VERSION 5.8 ;
BUSBITCHARS "[]" ;
DIVIDERCHAR "/" ;
UNITS
    DATABASE MICRONS 1000 ;
END UNITS

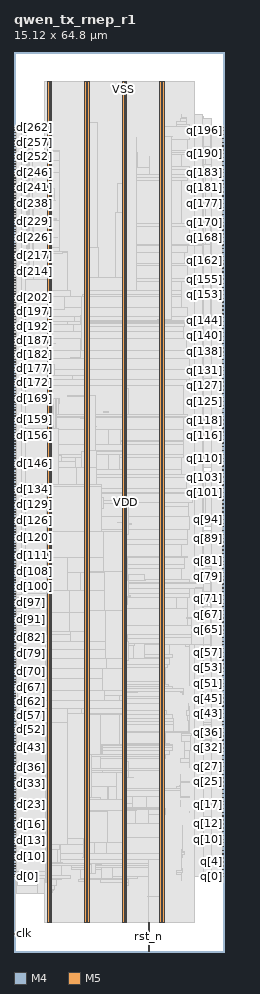
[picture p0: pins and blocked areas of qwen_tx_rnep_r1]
MACRO qwen_tx_rnep_r1
  FOREIGN qwen_tx_rnep_r1 0 0 ;
  CLASS BLOCK ;
  SIZE 15.12 BY 64.8 ;
  PIN clk
    DIRECTION INPUT ;
    USE SIGNAL ;
    PORT
      LAYER M4 ;
        RECT  0.054 1.296 0.138 1.32 ;
    END
    PORT
      LAYER M4 ;
        RECT  0.108 1.296 0.227 1.416 ;
    END
  END clk
  PIN d[0]
    DIRECTION INPUT ;
    USE SIGNAL ;
    PORT
      LAYER M4 ;
        RECT  0.054 5.424 0.138 5.448 ;
    END
  END d[0]
  PIN d[100]
    DIRECTION INPUT ;
    USE SIGNAL ;
    PORT
      LAYER M4 ;
        RECT  0.054 25.776 0.138 25.8 ;
    END
  END d[100]
  PIN d[101]
    DIRECTION INPUT ;
    USE SIGNAL ;
    PORT
      LAYER M4 ;
        RECT  0.054 25.968 0.138 25.992 ;
    END
  END d[101]
  PIN d[102]
    DIRECTION INPUT ;
    USE SIGNAL ;
    PORT
      LAYER M4 ;
        RECT  0.054 26.16 0.138 26.184 ;
    END
  END d[102]
  PIN d[103]
    DIRECTION INPUT ;
    USE SIGNAL ;
    PORT
      LAYER M4 ;
        RECT  0.054 26.4 0.138 26.424 ;
    END
  END d[103]
  PIN d[104]
    DIRECTION INPUT ;
    USE SIGNAL ;
    PORT
      LAYER M4 ;
        RECT  0.054 26.592 0.138 26.616 ;
    END
  END d[104]
  PIN d[105]
    DIRECTION INPUT ;
    USE SIGNAL ;
    PORT
      LAYER M4 ;
        RECT  0.054 26.784 0.138 26.808 ;
    END
  END d[105]
  PIN d[106]
    DIRECTION INPUT ;
    USE SIGNAL ;
    PORT
      LAYER M4 ;
        RECT  0.054 26.976 0.138 27 ;
    END
  END d[106]
  PIN d[107]
    DIRECTION INPUT ;
    USE SIGNAL ;
    PORT
      LAYER M4 ;
        RECT  0.054 27.168 0.138 27.192 ;
    END
  END d[107]
  PIN d[108]
    DIRECTION INPUT ;
    USE SIGNAL ;
    PORT
      LAYER M4 ;
        RECT  0.054 27.408 0.138 27.432 ;
    END
  END d[108]
  PIN d[109]
    DIRECTION INPUT ;
    USE SIGNAL ;
    PORT
      LAYER M4 ;
        RECT  0.054 27.6 0.138 27.624 ;
    END
  END d[109]
  PIN d[10]
    DIRECTION INPUT ;
    USE SIGNAL ;
    PORT
      LAYER M4 ;
        RECT  0.054 7.44 0.138 7.464 ;
    END
  END d[10]
  PIN d[110]
    DIRECTION INPUT ;
    USE SIGNAL ;
    PORT
      LAYER M4 ;
        RECT  0.054 27.792 0.138 27.816 ;
    END
  END d[110]
  PIN d[111]
    DIRECTION INPUT ;
    USE SIGNAL ;
    PORT
      LAYER M4 ;
        RECT  0.054 27.984 0.138 28.008 ;
    END
  END d[111]
  PIN d[112]
    DIRECTION INPUT ;
    USE SIGNAL ;
    PORT
      LAYER M4 ;
        RECT  0.054 28.224 0.138 28.248 ;
    END
  END d[112]
  PIN d[113]
    DIRECTION INPUT ;
    USE SIGNAL ;
    PORT
      LAYER M4 ;
        RECT  0.054 28.416 0.138 28.44 ;
    END
  END d[113]
  PIN d[114]
    DIRECTION INPUT ;
    USE SIGNAL ;
    PORT
      LAYER M4 ;
        RECT  0.054 28.608 0.138 28.632 ;
    END
  END d[114]
  PIN d[115]
    DIRECTION INPUT ;
    USE SIGNAL ;
    PORT
      LAYER M4 ;
        RECT  0.054 28.8 0.138 28.824 ;
    END
  END d[115]
  PIN d[116]
    DIRECTION INPUT ;
    USE SIGNAL ;
    PORT
      LAYER M4 ;
        RECT  0.054 29.04 0.138 29.064 ;
    END
  END d[116]
  PIN d[117]
    DIRECTION INPUT ;
    USE SIGNAL ;
    PORT
      LAYER M4 ;
        RECT  0.054 29.232 0.138 29.256 ;
    END
  END d[117]
  PIN d[118]
    DIRECTION INPUT ;
    USE SIGNAL ;
    PORT
      LAYER M4 ;
        RECT  0.054 29.424 0.138 29.448 ;
    END
  END d[118]
  PIN d[119]
    DIRECTION INPUT ;
    USE SIGNAL ;
    PORT
      LAYER M4 ;
        RECT  0.054 29.616 0.138 29.64 ;
    END
  END d[119]
  PIN d[11]
    DIRECTION INPUT ;
    USE SIGNAL ;
    PORT
      LAYER M4 ;
        RECT  0.054 7.632 0.138 7.656 ;
    END
  END d[11]
  PIN d[120]
    DIRECTION INPUT ;
    USE SIGNAL ;
    PORT
      LAYER M4 ;
        RECT  0.054 29.856 0.138 29.88 ;
    END
  END d[120]
  PIN d[121]
    DIRECTION INPUT ;
    USE SIGNAL ;
    PORT
      LAYER M4 ;
        RECT  0.054 30.048 0.138 30.072 ;
    END
  END d[121]
  PIN d[122]
    DIRECTION INPUT ;
    USE SIGNAL ;
    PORT
      LAYER M4 ;
        RECT  0.054 30.24 0.138 30.264 ;
    END
  END d[122]
  PIN d[123]
    DIRECTION INPUT ;
    USE SIGNAL ;
    PORT
      LAYER M4 ;
        RECT  0.054 30.432 0.138 30.456 ;
    END
  END d[123]
  PIN d[124]
    DIRECTION INPUT ;
    USE SIGNAL ;
    PORT
      LAYER M4 ;
        RECT  0.054 30.672 0.138 30.696 ;
    END
  END d[124]
  PIN d[125]
    DIRECTION INPUT ;
    USE SIGNAL ;
    PORT
      LAYER M4 ;
        RECT  0.054 30.864 0.138 30.888 ;
    END
  END d[125]
  PIN d[126]
    DIRECTION INPUT ;
    USE SIGNAL ;
    PORT
      LAYER M4 ;
        RECT  0.054 31.056 0.138 31.08 ;
    END
  END d[126]
  PIN d[127]
    DIRECTION INPUT ;
    USE SIGNAL ;
    PORT
      LAYER M4 ;
        RECT  0.054 31.248 0.138 31.272 ;
    END
  END d[127]
  PIN d[128]
    DIRECTION INPUT ;
    USE SIGNAL ;
    PORT
      LAYER M4 ;
        RECT  0.054 31.488 0.138 31.512 ;
    END
  END d[128]
  PIN d[129]
    DIRECTION INPUT ;
    USE SIGNAL ;
    PORT
      LAYER M4 ;
        RECT  0.054 31.68 0.138 31.704 ;
    END
  END d[129]
  PIN d[12]
    DIRECTION INPUT ;
    USE SIGNAL ;
    PORT
      LAYER M4 ;
        RECT  0.054 7.824 0.138 7.848 ;
    END
  END d[12]
  PIN d[130]
    DIRECTION INPUT ;
    USE SIGNAL ;
    PORT
      LAYER M4 ;
        RECT  0.054 31.872 0.138 31.896 ;
    END
  END d[130]
  PIN d[131]
    DIRECTION INPUT ;
    USE SIGNAL ;
    PORT
      LAYER M4 ;
        RECT  0.054 32.064 0.138 32.088 ;
    END
  END d[131]
  PIN d[132]
    DIRECTION INPUT ;
    USE SIGNAL ;
    PORT
      LAYER M4 ;
        RECT  0.054 32.304 0.138 32.328 ;
    END
  END d[132]
  PIN d[133]
    DIRECTION INPUT ;
    USE SIGNAL ;
    PORT
      LAYER M4 ;
        RECT  0.054 32.496 0.138 32.52 ;
    END
  END d[133]
  PIN d[134]
    DIRECTION INPUT ;
    USE SIGNAL ;
    PORT
      LAYER M4 ;
        RECT  0.054 32.688 0.138 32.712 ;
    END
  END d[134]
  PIN d[135]
    DIRECTION INPUT ;
    USE SIGNAL ;
    PORT
      LAYER M4 ;
        RECT  0.054 32.88 0.138 32.904 ;
    END
  END d[135]
  PIN d[136]
    DIRECTION INPUT ;
    USE SIGNAL ;
    PORT
      LAYER M4 ;
        RECT  0.054 33.12 0.138 33.144 ;
    END
  END d[136]
  PIN d[137]
    DIRECTION INPUT ;
    USE SIGNAL ;
    PORT
      LAYER M4 ;
        RECT  0.054 33.312 0.138 33.336 ;
    END
  END d[137]
  PIN d[138]
    DIRECTION INPUT ;
    USE SIGNAL ;
    PORT
      LAYER M4 ;
        RECT  0.054 33.504 0.138 33.528 ;
    END
  END d[138]
  PIN d[139]
    DIRECTION INPUT ;
    USE SIGNAL ;
    PORT
      LAYER M4 ;
        RECT  0.054 33.696 0.138 33.72 ;
    END
  END d[139]
  PIN d[13]
    DIRECTION INPUT ;
    USE SIGNAL ;
    PORT
      LAYER M4 ;
        RECT  0.054 8.016 0.138 8.04 ;
    END
  END d[13]
  PIN d[140]
    DIRECTION INPUT ;
    USE SIGNAL ;
    PORT
      LAYER M4 ;
        RECT  0.054 33.936 0.138 33.96 ;
    END
  END d[140]
  PIN d[141]
    DIRECTION INPUT ;
    USE SIGNAL ;
    PORT
      LAYER M4 ;
        RECT  0.054 34.128 0.138 34.152 ;
    END
  END d[141]
  PIN d[142]
    DIRECTION INPUT ;
    USE SIGNAL ;
    PORT
      LAYER M4 ;
        RECT  0.054 34.32 0.138 34.344 ;
    END
  END d[142]
  PIN d[143]
    DIRECTION INPUT ;
    USE SIGNAL ;
    PORT
      LAYER M4 ;
        RECT  0.054 34.512 0.138 34.536 ;
    END
  END d[143]
  PIN d[144]
    DIRECTION INPUT ;
    USE SIGNAL ;
    PORT
      LAYER M4 ;
        RECT  0.054 34.752 0.138 34.776 ;
    END
  END d[144]
  PIN d[145]
    DIRECTION INPUT ;
    USE SIGNAL ;
    PORT
      LAYER M4 ;
        RECT  0.054 34.944 0.138 34.968 ;
    END
  END d[145]
  PIN d[146]
    DIRECTION INPUT ;
    USE SIGNAL ;
    PORT
      LAYER M4 ;
        RECT  0.054 35.136 0.138 35.16 ;
    END
  END d[146]
  PIN d[147]
    DIRECTION INPUT ;
    USE SIGNAL ;
    PORT
      LAYER M4 ;
        RECT  0.054 35.328 0.138 35.352 ;
    END
  END d[147]
  PIN d[148]
    DIRECTION INPUT ;
    USE SIGNAL ;
    PORT
      LAYER M4 ;
        RECT  0.054 35.568 0.138 35.592 ;
    END
  END d[148]
  PIN d[149]
    DIRECTION INPUT ;
    USE SIGNAL ;
    PORT
      LAYER M4 ;
        RECT  0.054 35.76 0.138 35.784 ;
    END
  END d[149]
  PIN d[14]
    DIRECTION INPUT ;
    USE SIGNAL ;
    PORT
      LAYER M4 ;
        RECT  0.054 8.256 0.138 8.28 ;
    END
  END d[14]
  PIN d[150]
    DIRECTION INPUT ;
    USE SIGNAL ;
    PORT
      LAYER M4 ;
        RECT  0.054 35.952 0.138 35.976 ;
    END
  END d[150]
  PIN d[151]
    DIRECTION INPUT ;
    USE SIGNAL ;
    PORT
      LAYER M4 ;
        RECT  0.054 36.144 0.138 36.168 ;
    END
  END d[151]
  PIN d[152]
    DIRECTION INPUT ;
    USE SIGNAL ;
    PORT
      LAYER M4 ;
        RECT  0.054 36.384 0.138 36.408 ;
    END
  END d[152]
  PIN d[153]
    DIRECTION INPUT ;
    USE SIGNAL ;
    PORT
      LAYER M4 ;
        RECT  0.054 36.576 0.138 36.6 ;
    END
  END d[153]
  PIN d[154]
    DIRECTION INPUT ;
    USE SIGNAL ;
    PORT
      LAYER M4 ;
        RECT  0.054 36.768 0.138 36.792 ;
    END
  END d[154]
  PIN d[155]
    DIRECTION INPUT ;
    USE SIGNAL ;
    PORT
      LAYER M4 ;
        RECT  0.054 36.96 0.138 36.984 ;
    END
  END d[155]
  PIN d[156]
    DIRECTION INPUT ;
    USE SIGNAL ;
    PORT
      LAYER M4 ;
        RECT  0.054 37.2 0.138 37.224 ;
    END
  END d[156]
  PIN d[157]
    DIRECTION INPUT ;
    USE SIGNAL ;
    PORT
      LAYER M4 ;
        RECT  0.054 37.392 0.138 37.416 ;
    END
  END d[157]
  PIN d[158]
    DIRECTION INPUT ;
    USE SIGNAL ;
    PORT
      LAYER M4 ;
        RECT  0.054 37.584 0.138 37.608 ;
    END
  END d[158]
  PIN d[159]
    DIRECTION INPUT ;
    USE SIGNAL ;
    PORT
      LAYER M4 ;
        RECT  0.054 37.776 0.138 37.8 ;
    END
  END d[159]
  PIN d[15]
    DIRECTION INPUT ;
    USE SIGNAL ;
    PORT
      LAYER M4 ;
        RECT  0.054 8.448 0.138 8.472 ;
    END
  END d[15]
  PIN d[160]
    DIRECTION INPUT ;
    USE SIGNAL ;
    PORT
      LAYER M4 ;
        RECT  0.054 37.968 0.138 37.992 ;
    END
  END d[160]
  PIN d[161]
    DIRECTION INPUT ;
    USE SIGNAL ;
    PORT
      LAYER M4 ;
        RECT  0.054 38.208 0.138 38.232 ;
    END
  END d[161]
  PIN d[162]
    DIRECTION INPUT ;
    USE SIGNAL ;
    PORT
      LAYER M4 ;
        RECT  0.054 38.4 0.138 38.424 ;
    END
  END d[162]
  PIN d[163]
    DIRECTION INPUT ;
    USE SIGNAL ;
    PORT
      LAYER M4 ;
        RECT  0.054 38.592 0.138 38.616 ;
    END
  END d[163]
  PIN d[164]
    DIRECTION INPUT ;
    USE SIGNAL ;
    PORT
      LAYER M4 ;
        RECT  0.054 38.784 0.138 38.808 ;
    END
  END d[164]
  PIN d[165]
    DIRECTION INPUT ;
    USE SIGNAL ;
    PORT
      LAYER M4 ;
        RECT  0.054 39.024 0.138 39.048 ;
    END
  END d[165]
  PIN d[166]
    DIRECTION INPUT ;
    USE SIGNAL ;
    PORT
      LAYER M4 ;
        RECT  0.054 39.216 0.138 39.24 ;
    END
  END d[166]
  PIN d[167]
    DIRECTION INPUT ;
    USE SIGNAL ;
    PORT
      LAYER M4 ;
        RECT  0.054 39.408 0.138 39.432 ;
    END
  END d[167]
  PIN d[168]
    DIRECTION INPUT ;
    USE SIGNAL ;
    PORT
      LAYER M4 ;
        RECT  0.054 39.6 0.138 39.624 ;
    END
  END d[168]
  PIN d[169]
    DIRECTION INPUT ;
    USE SIGNAL ;
    PORT
      LAYER M4 ;
        RECT  0.054 39.84 0.138 39.864 ;
    END
  END d[169]
  PIN d[16]
    DIRECTION INPUT ;
    USE SIGNAL ;
    PORT
      LAYER M4 ;
        RECT  0.054 8.64 0.138 8.664 ;
    END
  END d[16]
  PIN d[170]
    DIRECTION INPUT ;
    USE SIGNAL ;
    PORT
      LAYER M4 ;
        RECT  0.054 40.032 0.138 40.056 ;
    END
  END d[170]
  PIN d[171]
    DIRECTION INPUT ;
    USE SIGNAL ;
    PORT
      LAYER M4 ;
        RECT  0.054 40.224 0.138 40.248 ;
    END
  END d[171]
  PIN d[172]
    DIRECTION INPUT ;
    USE SIGNAL ;
    PORT
      LAYER M4 ;
        RECT  0.054 40.416 0.138 40.44 ;
    END
  END d[172]
  PIN d[173]
    DIRECTION INPUT ;
    USE SIGNAL ;
    PORT
      LAYER M4 ;
        RECT  0.054 40.656 0.138 40.68 ;
    END
  END d[173]
  PIN d[174]
    DIRECTION INPUT ;
    USE SIGNAL ;
    PORT
      LAYER M4 ;
        RECT  0.054 40.848 0.138 40.872 ;
    END
  END d[174]
  PIN d[175]
    DIRECTION INPUT ;
    USE SIGNAL ;
    PORT
      LAYER M4 ;
        RECT  0.054 41.04 0.138 41.064 ;
    END
  END d[175]
  PIN d[176]
    DIRECTION INPUT ;
    USE SIGNAL ;
    PORT
      LAYER M4 ;
        RECT  0.054 41.232 0.138 41.256 ;
    END
  END d[176]
  PIN d[177]
    DIRECTION INPUT ;
    USE SIGNAL ;
    PORT
      LAYER M4 ;
        RECT  0.054 41.472 0.138 41.496 ;
    END
  END d[177]
  PIN d[178]
    DIRECTION INPUT ;
    USE SIGNAL ;
    PORT
      LAYER M4 ;
        RECT  0.054 41.664 0.138 41.688 ;
    END
  END d[178]
  PIN d[179]
    DIRECTION INPUT ;
    USE SIGNAL ;
    PORT
      LAYER M4 ;
        RECT  0.054 41.856 0.138 41.88 ;
    END
  END d[179]
  PIN d[17]
    DIRECTION INPUT ;
    USE SIGNAL ;
    PORT
      LAYER M4 ;
        RECT  0.054 8.832 0.138 8.856 ;
    END
  END d[17]
  PIN d[180]
    DIRECTION INPUT ;
    USE SIGNAL ;
    PORT
      LAYER M4 ;
        RECT  0.054 42.048 0.138 42.072 ;
    END
  END d[180]
  PIN d[181]
    DIRECTION INPUT ;
    USE SIGNAL ;
    PORT
      LAYER M4 ;
        RECT  0.054 42.288 0.138 42.312 ;
    END
  END d[181]
  PIN d[182]
    DIRECTION INPUT ;
    USE SIGNAL ;
    PORT
      LAYER M4 ;
        RECT  0.054 42.48 0.138 42.504 ;
    END
  END d[182]
  PIN d[183]
    DIRECTION INPUT ;
    USE SIGNAL ;
    PORT
      LAYER M4 ;
        RECT  0.054 42.672 0.138 42.696 ;
    END
  END d[183]
  PIN d[184]
    DIRECTION INPUT ;
    USE SIGNAL ;
    PORT
      LAYER M4 ;
        RECT  0.054 42.864 0.138 42.888 ;
    END
  END d[184]
  PIN d[185]
    DIRECTION INPUT ;
    USE SIGNAL ;
    PORT
      LAYER M4 ;
        RECT  0.054 43.104 0.138 43.128 ;
    END
  END d[185]
  PIN d[186]
    DIRECTION INPUT ;
    USE SIGNAL ;
    PORT
      LAYER M4 ;
        RECT  0.054 43.296 0.138 43.32 ;
    END
  END d[186]
  PIN d[187]
    DIRECTION INPUT ;
    USE SIGNAL ;
    PORT
      LAYER M4 ;
        RECT  0.054 43.488 0.138 43.512 ;
    END
  END d[187]
  PIN d[188]
    DIRECTION INPUT ;
    USE SIGNAL ;
    PORT
      LAYER M4 ;
        RECT  0.054 43.68 0.138 43.704 ;
    END
  END d[188]
  PIN d[189]
    DIRECTION INPUT ;
    USE SIGNAL ;
    PORT
      LAYER M4 ;
        RECT  0.054 43.92 0.138 43.944 ;
    END
  END d[189]
  PIN d[18]
    DIRECTION INPUT ;
    USE SIGNAL ;
    PORT
      LAYER M4 ;
        RECT  0.054 9.072 0.138 9.096 ;
    END
  END d[18]
  PIN d[190]
    DIRECTION INPUT ;
    USE SIGNAL ;
    PORT
      LAYER M4 ;
        RECT  0.054 44.112 0.138 44.136 ;
    END
  END d[190]
  PIN d[191]
    DIRECTION INPUT ;
    USE SIGNAL ;
    PORT
      LAYER M4 ;
        RECT  0.054 44.304 0.138 44.328 ;
    END
  END d[191]
  PIN d[192]
    DIRECTION INPUT ;
    USE SIGNAL ;
    PORT
      LAYER M4 ;
        RECT  0.054 44.496 0.138 44.52 ;
    END
  END d[192]
  PIN d[193]
    DIRECTION INPUT ;
    USE SIGNAL ;
    PORT
      LAYER M4 ;
        RECT  0.054 44.736 0.138 44.76 ;
    END
  END d[193]
  PIN d[194]
    DIRECTION INPUT ;
    USE SIGNAL ;
    PORT
      LAYER M4 ;
        RECT  0.054 44.928 0.138 44.952 ;
    END
  END d[194]
  PIN d[195]
    DIRECTION INPUT ;
    USE SIGNAL ;
    PORT
      LAYER M4 ;
        RECT  0.054 45.12 0.138 45.144 ;
    END
  END d[195]
  PIN d[196]
    DIRECTION INPUT ;
    USE SIGNAL ;
    PORT
      LAYER M4 ;
        RECT  0.054 45.312 0.138 45.336 ;
    END
  END d[196]
  PIN d[197]
    DIRECTION INPUT ;
    USE SIGNAL ;
    PORT
      LAYER M4 ;
        RECT  0.054 45.552 0.138 45.576 ;
    END
  END d[197]
  PIN d[198]
    DIRECTION INPUT ;
    USE SIGNAL ;
    PORT
      LAYER M4 ;
        RECT  0.054 45.744 0.138 45.768 ;
    END
  END d[198]
  PIN d[199]
    DIRECTION INPUT ;
    USE SIGNAL ;
    PORT
      LAYER M4 ;
        RECT  0.054 45.936 0.138 45.96 ;
    END
  END d[199]
  PIN d[19]
    DIRECTION INPUT ;
    USE SIGNAL ;
    PORT
      LAYER M4 ;
        RECT  0.054 9.264 0.138 9.288 ;
    END
  END d[19]
  PIN d[1]
    DIRECTION INPUT ;
    USE SIGNAL ;
    PORT
      LAYER M4 ;
        RECT  0.054 5.568 0.138 5.592 ;
    END
  END d[1]
  PIN d[200]
    DIRECTION INPUT ;
    USE SIGNAL ;
    PORT
      LAYER M4 ;
        RECT  0.054 46.128 0.138 46.152 ;
    END
  END d[200]
  PIN d[201]
    DIRECTION INPUT ;
    USE SIGNAL ;
    PORT
      LAYER M4 ;
        RECT  0.054 46.368 0.138 46.392 ;
    END
  END d[201]
  PIN d[202]
    DIRECTION INPUT ;
    USE SIGNAL ;
    PORT
      LAYER M4 ;
        RECT  0.054 46.56 0.138 46.584 ;
    END
  END d[202]
  PIN d[203]
    DIRECTION INPUT ;
    USE SIGNAL ;
    PORT
      LAYER M4 ;
        RECT  0.054 46.752 0.138 46.776 ;
    END
  END d[203]
  PIN d[204]
    DIRECTION INPUT ;
    USE SIGNAL ;
    PORT
      LAYER M4 ;
        RECT  0.054 46.944 0.138 46.968 ;
    END
  END d[204]
  PIN d[205]
    DIRECTION INPUT ;
    USE SIGNAL ;
    PORT
      LAYER M4 ;
        RECT  0.054 47.184 0.138 47.208 ;
    END
  END d[205]
  PIN d[206]
    DIRECTION INPUT ;
    USE SIGNAL ;
    PORT
      LAYER M4 ;
        RECT  0.054 47.376 0.138 47.4 ;
    END
  END d[206]
  PIN d[207]
    DIRECTION INPUT ;
    USE SIGNAL ;
    PORT
      LAYER M4 ;
        RECT  0.054 47.568 0.138 47.592 ;
    END
  END d[207]
  PIN d[208]
    DIRECTION INPUT ;
    USE SIGNAL ;
    PORT
      LAYER M4 ;
        RECT  0.054 47.76 0.138 47.784 ;
    END
  END d[208]
  PIN d[209]
    DIRECTION INPUT ;
    USE SIGNAL ;
    PORT
      LAYER M4 ;
        RECT  0.054 48 0.138 48.024 ;
    END
  END d[209]
  PIN d[20]
    DIRECTION INPUT ;
    USE SIGNAL ;
    PORT
      LAYER M4 ;
        RECT  0.054 9.456 0.138 9.48 ;
    END
  END d[20]
  PIN d[210]
    DIRECTION INPUT ;
    USE SIGNAL ;
    PORT
      LAYER M4 ;
        RECT  0.054 48.192 0.138 48.216 ;
    END
  END d[210]
  PIN d[211]
    DIRECTION INPUT ;
    USE SIGNAL ;
    PORT
      LAYER M4 ;
        RECT  0.054 48.384 0.138 48.408 ;
    END
  END d[211]
  PIN d[212]
    DIRECTION INPUT ;
    USE SIGNAL ;
    PORT
      LAYER M4 ;
        RECT  0.054 48.576 0.138 48.6 ;
    END
  END d[212]
  PIN d[213]
    DIRECTION INPUT ;
    USE SIGNAL ;
    PORT
      LAYER M4 ;
        RECT  0.054 48.768 0.138 48.792 ;
    END
  END d[213]
  PIN d[214]
    DIRECTION INPUT ;
    USE SIGNAL ;
    PORT
      LAYER M4 ;
        RECT  0.054 49.008 0.138 49.032 ;
    END
  END d[214]
  PIN d[215]
    DIRECTION INPUT ;
    USE SIGNAL ;
    PORT
      LAYER M4 ;
        RECT  0.054 49.2 0.138 49.224 ;
    END
  END d[215]
  PIN d[216]
    DIRECTION INPUT ;
    USE SIGNAL ;
    PORT
      LAYER M4 ;
        RECT  0.054 49.392 0.138 49.416 ;
    END
  END d[216]
  PIN d[217]
    DIRECTION INPUT ;
    USE SIGNAL ;
    PORT
      LAYER M4 ;
        RECT  0.054 49.584 0.138 49.608 ;
    END
  END d[217]
  PIN d[218]
    DIRECTION INPUT ;
    USE SIGNAL ;
    PORT
      LAYER M4 ;
        RECT  0.054 49.824 0.138 49.848 ;
    END
  END d[218]
  PIN d[219]
    DIRECTION INPUT ;
    USE SIGNAL ;
    PORT
      LAYER M4 ;
        RECT  0.054 50.016 0.138 50.04 ;
    END
  END d[219]
  PIN d[21]
    DIRECTION INPUT ;
    USE SIGNAL ;
    PORT
      LAYER M4 ;
        RECT  0.054 9.648 0.138 9.672 ;
    END
  END d[21]
  PIN d[220]
    DIRECTION INPUT ;
    USE SIGNAL ;
    PORT
      LAYER M4 ;
        RECT  0.054 50.208 0.138 50.232 ;
    END
  END d[220]
  PIN d[221]
    DIRECTION INPUT ;
    USE SIGNAL ;
    PORT
      LAYER M4 ;
        RECT  0.054 50.4 0.138 50.424 ;
    END
  END d[221]
  PIN d[222]
    DIRECTION INPUT ;
    USE SIGNAL ;
    PORT
      LAYER M4 ;
        RECT  0.054 50.64 0.138 50.664 ;
    END
  END d[222]
  PIN d[223]
    DIRECTION INPUT ;
    USE SIGNAL ;
    PORT
      LAYER M4 ;
        RECT  0.054 50.832 0.138 50.856 ;
    END
  END d[223]
  PIN d[224]
    DIRECTION INPUT ;
    USE SIGNAL ;
    PORT
      LAYER M4 ;
        RECT  0.054 51.024 0.138 51.048 ;
    END
  END d[224]
  PIN d[225]
    DIRECTION INPUT ;
    USE SIGNAL ;
    PORT
      LAYER M4 ;
        RECT  0.054 51.216 0.138 51.24 ;
    END
  END d[225]
  PIN d[226]
    DIRECTION INPUT ;
    USE SIGNAL ;
    PORT
      LAYER M4 ;
        RECT  0.054 51.456 0.138 51.48 ;
    END
  END d[226]
  PIN d[227]
    DIRECTION INPUT ;
    USE SIGNAL ;
    PORT
      LAYER M4 ;
        RECT  0.054 51.648 0.138 51.672 ;
    END
  END d[227]
  PIN d[228]
    DIRECTION INPUT ;
    USE SIGNAL ;
    PORT
      LAYER M4 ;
        RECT  0.054 51.84 0.138 51.864 ;
    END
  END d[228]
  PIN d[229]
    DIRECTION INPUT ;
    USE SIGNAL ;
    PORT
      LAYER M4 ;
        RECT  0.054 52.032 0.138 52.056 ;
    END
  END d[229]
  PIN d[22]
    DIRECTION INPUT ;
    USE SIGNAL ;
    PORT
      LAYER M4 ;
        RECT  0.054 9.888 0.138 9.912 ;
    END
  END d[22]
  PIN d[230]
    DIRECTION INPUT ;
    USE SIGNAL ;
    PORT
      LAYER M4 ;
        RECT  0.054 52.272 0.138 52.296 ;
    END
  END d[230]
  PIN d[231]
    DIRECTION INPUT ;
    USE SIGNAL ;
    PORT
      LAYER M4 ;
        RECT  0.054 52.464 0.138 52.488 ;
    END
  END d[231]
  PIN d[232]
    DIRECTION INPUT ;
    USE SIGNAL ;
    PORT
      LAYER M4 ;
        RECT  0.054 52.656 0.138 52.68 ;
    END
  END d[232]
  PIN d[233]
    DIRECTION INPUT ;
    USE SIGNAL ;
    PORT
      LAYER M4 ;
        RECT  0.054 52.848 0.138 52.872 ;
    END
  END d[233]
  PIN d[234]
    DIRECTION INPUT ;
    USE SIGNAL ;
    PORT
      LAYER M4 ;
        RECT  0.054 53.088 0.138 53.112 ;
    END
  END d[234]
  PIN d[235]
    DIRECTION INPUT ;
    USE SIGNAL ;
    PORT
      LAYER M4 ;
        RECT  0.054 53.28 0.138 53.304 ;
    END
  END d[235]
  PIN d[236]
    DIRECTION INPUT ;
    USE SIGNAL ;
    PORT
      LAYER M4 ;
        RECT  0.054 53.472 0.138 53.496 ;
    END
  END d[236]
  PIN d[237]
    DIRECTION INPUT ;
    USE SIGNAL ;
    PORT
      LAYER M4 ;
        RECT  0.054 53.664 0.138 53.688 ;
    END
  END d[237]
  PIN d[238]
    DIRECTION INPUT ;
    USE SIGNAL ;
    PORT
      LAYER M4 ;
        RECT  0.054 53.904 0.138 53.928 ;
    END
  END d[238]
  PIN d[239]
    DIRECTION INPUT ;
    USE SIGNAL ;
    PORT
      LAYER M4 ;
        RECT  0.054 54.096 0.138 54.12 ;
    END
  END d[239]
  PIN d[23]
    DIRECTION INPUT ;
    USE SIGNAL ;
    PORT
      LAYER M4 ;
        RECT  0.054 10.08 0.138 10.104 ;
    END
  END d[23]
  PIN d[240]
    DIRECTION INPUT ;
    USE SIGNAL ;
    PORT
      LAYER M4 ;
        RECT  0.054 54.288 0.138 54.312 ;
    END
  END d[240]
  PIN d[241]
    DIRECTION INPUT ;
    USE SIGNAL ;
    PORT
      LAYER M4 ;
        RECT  0.054 54.48 0.138 54.504 ;
    END
  END d[241]
  PIN d[242]
    DIRECTION INPUT ;
    USE SIGNAL ;
    PORT
      LAYER M4 ;
        RECT  0.054 54.72 0.138 54.744 ;
    END
  END d[242]
  PIN d[243]
    DIRECTION INPUT ;
    USE SIGNAL ;
    PORT
      LAYER M4 ;
        RECT  0.054 54.912 0.138 54.936 ;
    END
  END d[243]
  PIN d[244]
    DIRECTION INPUT ;
    USE SIGNAL ;
    PORT
      LAYER M4 ;
        RECT  0.054 55.104 0.138 55.128 ;
    END
  END d[244]
  PIN d[245]
    DIRECTION INPUT ;
    USE SIGNAL ;
    PORT
      LAYER M4 ;
        RECT  0.054 55.296 0.138 55.32 ;
    END
  END d[245]
  PIN d[246]
    DIRECTION INPUT ;
    USE SIGNAL ;
    PORT
      LAYER M4 ;
        RECT  0.054 55.536 0.138 55.56 ;
    END
  END d[246]
  PIN d[247]
    DIRECTION INPUT ;
    USE SIGNAL ;
    PORT
      LAYER M4 ;
        RECT  0.054 55.728 0.138 55.752 ;
    END
  END d[247]
  PIN d[248]
    DIRECTION INPUT ;
    USE SIGNAL ;
    PORT
      LAYER M4 ;
        RECT  0.054 55.92 0.138 55.944 ;
    END
  END d[248]
  PIN d[249]
    DIRECTION INPUT ;
    USE SIGNAL ;
    PORT
      LAYER M4 ;
        RECT  0.054 56.112 0.138 56.136 ;
    END
  END d[249]
  PIN d[24]
    DIRECTION INPUT ;
    USE SIGNAL ;
    PORT
      LAYER M4 ;
        RECT  0.054 10.272 0.138 10.296 ;
    END
  END d[24]
  PIN d[250]
    DIRECTION INPUT ;
    USE SIGNAL ;
    PORT
      LAYER M4 ;
        RECT  0.054 56.352 0.138 56.376 ;
    END
  END d[250]
  PIN d[251]
    DIRECTION INPUT ;
    USE SIGNAL ;
    PORT
      LAYER M4 ;
        RECT  0.054 56.544 0.138 56.568 ;
    END
  END d[251]
  PIN d[252]
    DIRECTION INPUT ;
    USE SIGNAL ;
    PORT
      LAYER M4 ;
        RECT  0.054 56.736 0.138 56.76 ;
    END
  END d[252]
  PIN d[253]
    DIRECTION INPUT ;
    USE SIGNAL ;
    PORT
      LAYER M4 ;
        RECT  0.054 56.928 0.138 56.952 ;
    END
  END d[253]
  PIN d[254]
    DIRECTION INPUT ;
    USE SIGNAL ;
    PORT
      LAYER M4 ;
        RECT  0.054 57.168 0.138 57.192 ;
    END
  END d[254]
  PIN d[255]
    DIRECTION INPUT ;
    USE SIGNAL ;
    PORT
      LAYER M4 ;
        RECT  0.054 57.36 0.138 57.384 ;
    END
  END d[255]
  PIN d[256]
    DIRECTION INPUT ;
    USE SIGNAL ;
    PORT
      LAYER M4 ;
        RECT  0.054 57.552 0.138 57.576 ;
    END
  END d[256]
  PIN d[257]
    DIRECTION INPUT ;
    USE SIGNAL ;
    PORT
      LAYER M4 ;
        RECT  0.054 57.744 0.138 57.768 ;
    END
  END d[257]
  PIN d[258]
    DIRECTION INPUT ;
    USE SIGNAL ;
    PORT
      LAYER M4 ;
        RECT  0.054 57.984 0.138 58.008 ;
    END
  END d[258]
  PIN d[259]
    DIRECTION INPUT ;
    USE SIGNAL ;
    PORT
      LAYER M4 ;
        RECT  0.054 58.176 0.138 58.2 ;
    END
  END d[259]
  PIN d[25]
    DIRECTION INPUT ;
    USE SIGNAL ;
    PORT
      LAYER M4 ;
        RECT  0.054 10.464 0.138 10.488 ;
    END
  END d[25]
  PIN d[260]
    DIRECTION INPUT ;
    USE SIGNAL ;
    PORT
      LAYER M4 ;
        RECT  0.054 58.368 0.138 58.392 ;
    END
  END d[260]
  PIN d[261]
    DIRECTION INPUT ;
    USE SIGNAL ;
    PORT
      LAYER M4 ;
        RECT  0.054 58.56 0.138 58.584 ;
    END
  END d[261]
  PIN d[262]
    DIRECTION INPUT ;
    USE SIGNAL ;
    PORT
      LAYER M4 ;
        RECT  0.054 58.8 0.138 58.824 ;
    END
  END d[262]
  PIN d[263]
    DIRECTION INPUT ;
    USE SIGNAL ;
    PORT
      LAYER M4 ;
        RECT  0.054 58.992 0.138 59.016 ;
    END
  END d[263]
  PIN d[264]
    DIRECTION INPUT ;
    USE SIGNAL ;
    PORT
      LAYER M4 ;
        RECT  0.054 59.184 0.138 59.208 ;
    END
  END d[264]
  PIN d[265]
    DIRECTION INPUT ;
    USE SIGNAL ;
    PORT
      LAYER M4 ;
        RECT  0.054 59.376 0.138 59.4 ;
    END
  END d[265]
  PIN d[26]
    DIRECTION INPUT ;
    USE SIGNAL ;
    PORT
      LAYER M4 ;
        RECT  0.054 10.704 0.138 10.728 ;
    END
  END d[26]
  PIN d[27]
    DIRECTION INPUT ;
    USE SIGNAL ;
    PORT
      LAYER M4 ;
        RECT  0.054 10.896 0.138 10.92 ;
    END
  END d[27]
  PIN d[28]
    DIRECTION INPUT ;
    USE SIGNAL ;
    PORT
      LAYER M4 ;
        RECT  0.054 11.088 0.138 11.112 ;
    END
  END d[28]
  PIN d[29]
    DIRECTION INPUT ;
    USE SIGNAL ;
    PORT
      LAYER M4 ;
        RECT  0.054 11.28 0.138 11.304 ;
    END
  END d[29]
  PIN d[2]
    DIRECTION INPUT ;
    USE SIGNAL ;
    PORT
      LAYER M4 ;
        RECT  0.054 5.808 0.138 5.832 ;
    END
  END d[2]
  PIN d[30]
    DIRECTION INPUT ;
    USE SIGNAL ;
    PORT
      LAYER M4 ;
        RECT  0.054 11.52 0.138 11.544 ;
    END
  END d[30]
  PIN d[31]
    DIRECTION INPUT ;
    USE SIGNAL ;
    PORT
      LAYER M4 ;
        RECT  0.054 11.712 0.138 11.736 ;
    END
  END d[31]
  PIN d[32]
    DIRECTION INPUT ;
    USE SIGNAL ;
    PORT
      LAYER M4 ;
        RECT  0.054 11.904 0.138 11.928 ;
    END
  END d[32]
  PIN d[33]
    DIRECTION INPUT ;
    USE SIGNAL ;
    PORT
      LAYER M4 ;
        RECT  0.054 12.096 0.138 12.12 ;
    END
  END d[33]
  PIN d[34]
    DIRECTION INPUT ;
    USE SIGNAL ;
    PORT
      LAYER M4 ;
        RECT  0.054 12.336 0.138 12.36 ;
    END
  END d[34]
  PIN d[35]
    DIRECTION INPUT ;
    USE SIGNAL ;
    PORT
      LAYER M4 ;
        RECT  0.054 12.528 0.138 12.552 ;
    END
  END d[35]
  PIN d[36]
    DIRECTION INPUT ;
    USE SIGNAL ;
    PORT
      LAYER M4 ;
        RECT  0.054 12.72 0.138 12.744 ;
    END
  END d[36]
  PIN d[37]
    DIRECTION INPUT ;
    USE SIGNAL ;
    PORT
      LAYER M4 ;
        RECT  0.054 12.912 0.138 12.936 ;
    END
  END d[37]
  PIN d[38]
    DIRECTION INPUT ;
    USE SIGNAL ;
    PORT
      LAYER M4 ;
        RECT  0.054 13.152 0.138 13.176 ;
    END
  END d[38]
  PIN d[39]
    DIRECTION INPUT ;
    USE SIGNAL ;
    PORT
      LAYER M4 ;
        RECT  0.054 13.344 0.138 13.368 ;
    END
  END d[39]
  PIN d[3]
    DIRECTION INPUT ;
    USE SIGNAL ;
    PORT
      LAYER M4 ;
        RECT  0.054 6 0.138 6.024 ;
    END
  END d[3]
  PIN d[40]
    DIRECTION INPUT ;
    USE SIGNAL ;
    PORT
      LAYER M4 ;
        RECT  0.054 13.536 0.138 13.56 ;
    END
  END d[40]
  PIN d[41]
    DIRECTION INPUT ;
    USE SIGNAL ;
    PORT
      LAYER M4 ;
        RECT  0.054 13.728 0.138 13.752 ;
    END
  END d[41]
  PIN d[42]
    DIRECTION INPUT ;
    USE SIGNAL ;
    PORT
      LAYER M4 ;
        RECT  0.054 13.968 0.138 13.992 ;
    END
  END d[42]
  PIN d[43]
    DIRECTION INPUT ;
    USE SIGNAL ;
    PORT
      LAYER M4 ;
        RECT  0.054 14.16 0.138 14.184 ;
    END
  END d[43]
  PIN d[44]
    DIRECTION INPUT ;
    USE SIGNAL ;
    PORT
      LAYER M4 ;
        RECT  0.054 14.352 0.138 14.376 ;
    END
  END d[44]
  PIN d[45]
    DIRECTION INPUT ;
    USE SIGNAL ;
    PORT
      LAYER M4 ;
        RECT  0.054 14.544 0.138 14.568 ;
    END
  END d[45]
  PIN d[46]
    DIRECTION INPUT ;
    USE SIGNAL ;
    PORT
      LAYER M4 ;
        RECT  0.054 14.784 0.138 14.808 ;
    END
  END d[46]
  PIN d[47]
    DIRECTION INPUT ;
    USE SIGNAL ;
    PORT
      LAYER M4 ;
        RECT  0.054 14.976 0.138 15 ;
    END
  END d[47]
  PIN d[48]
    DIRECTION INPUT ;
    USE SIGNAL ;
    PORT
      LAYER M4 ;
        RECT  0.054 15.168 0.138 15.192 ;
    END
  END d[48]
  PIN d[49]
    DIRECTION INPUT ;
    USE SIGNAL ;
    PORT
      LAYER M4 ;
        RECT  0.054 15.36 0.138 15.384 ;
    END
  END d[49]
  PIN d[4]
    DIRECTION INPUT ;
    USE SIGNAL ;
    PORT
      LAYER M4 ;
        RECT  0.054 6.192 0.138 6.216 ;
    END
  END d[4]
  PIN d[50]
    DIRECTION INPUT ;
    USE SIGNAL ;
    PORT
      LAYER M4 ;
        RECT  0.054 15.6 0.138 15.624 ;
    END
  END d[50]
  PIN d[51]
    DIRECTION INPUT ;
    USE SIGNAL ;
    PORT
      LAYER M4 ;
        RECT  0.054 15.792 0.138 15.816 ;
    END
  END d[51]
  PIN d[52]
    DIRECTION INPUT ;
    USE SIGNAL ;
    PORT
      LAYER M4 ;
        RECT  0.054 15.984 0.138 16.008 ;
    END
  END d[52]
  PIN d[53]
    DIRECTION INPUT ;
    USE SIGNAL ;
    PORT
      LAYER M4 ;
        RECT  0.054 16.176 0.138 16.2 ;
    END
  END d[53]
  PIN d[54]
    DIRECTION INPUT ;
    USE SIGNAL ;
    PORT
      LAYER M4 ;
        RECT  0.054 16.368 0.138 16.392 ;
    END
  END d[54]
  PIN d[55]
    DIRECTION INPUT ;
    USE SIGNAL ;
    PORT
      LAYER M4 ;
        RECT  0.054 16.608 0.138 16.632 ;
    END
  END d[55]
  PIN d[56]
    DIRECTION INPUT ;
    USE SIGNAL ;
    PORT
      LAYER M4 ;
        RECT  0.054 16.8 0.138 16.824 ;
    END
  END d[56]
  PIN d[57]
    DIRECTION INPUT ;
    USE SIGNAL ;
    PORT
      LAYER M4 ;
        RECT  0.054 16.992 0.138 17.016 ;
    END
  END d[57]
  PIN d[58]
    DIRECTION INPUT ;
    USE SIGNAL ;
    PORT
      LAYER M4 ;
        RECT  0.054 17.184 0.138 17.208 ;
    END
  END d[58]
  PIN d[59]
    DIRECTION INPUT ;
    USE SIGNAL ;
    PORT
      LAYER M4 ;
        RECT  0.054 17.424 0.138 17.448 ;
    END
  END d[59]
  PIN d[5]
    DIRECTION INPUT ;
    USE SIGNAL ;
    PORT
      LAYER M4 ;
        RECT  0.054 6.384 0.138 6.408 ;
    END
  END d[5]
  PIN d[60]
    DIRECTION INPUT ;
    USE SIGNAL ;
    PORT
      LAYER M4 ;
        RECT  0.054 17.616 0.138 17.64 ;
    END
  END d[60]
  PIN d[61]
    DIRECTION INPUT ;
    USE SIGNAL ;
    PORT
      LAYER M4 ;
        RECT  0.054 17.808 0.138 17.832 ;
    END
  END d[61]
  PIN d[62]
    DIRECTION INPUT ;
    USE SIGNAL ;
    PORT
      LAYER M4 ;
        RECT  0.054 18 0.138 18.024 ;
    END
  END d[62]
  PIN d[63]
    DIRECTION INPUT ;
    USE SIGNAL ;
    PORT
      LAYER M4 ;
        RECT  0.054 18.24 0.138 18.264 ;
    END
  END d[63]
  PIN d[64]
    DIRECTION INPUT ;
    USE SIGNAL ;
    PORT
      LAYER M4 ;
        RECT  0.054 18.432 0.138 18.456 ;
    END
  END d[64]
  PIN d[65]
    DIRECTION INPUT ;
    USE SIGNAL ;
    PORT
      LAYER M4 ;
        RECT  0.054 18.624 0.138 18.648 ;
    END
  END d[65]
  PIN d[66]
    DIRECTION INPUT ;
    USE SIGNAL ;
    PORT
      LAYER M4 ;
        RECT  0.054 18.816 0.138 18.84 ;
    END
  END d[66]
  PIN d[67]
    DIRECTION INPUT ;
    USE SIGNAL ;
    PORT
      LAYER M4 ;
        RECT  0.054 19.056 0.138 19.08 ;
    END
  END d[67]
  PIN d[68]
    DIRECTION INPUT ;
    USE SIGNAL ;
    PORT
      LAYER M4 ;
        RECT  0.054 19.248 0.138 19.272 ;
    END
  END d[68]
  PIN d[69]
    DIRECTION INPUT ;
    USE SIGNAL ;
    PORT
      LAYER M4 ;
        RECT  0.054 19.44 0.138 19.464 ;
    END
  END d[69]
  PIN d[6]
    DIRECTION INPUT ;
    USE SIGNAL ;
    PORT
      LAYER M4 ;
        RECT  0.054 6.624 0.138 6.648 ;
    END
  END d[6]
  PIN d[70]
    DIRECTION INPUT ;
    USE SIGNAL ;
    PORT
      LAYER M4 ;
        RECT  0.054 19.632 0.138 19.656 ;
    END
  END d[70]
  PIN d[71]
    DIRECTION INPUT ;
    USE SIGNAL ;
    PORT
      LAYER M4 ;
        RECT  0.054 19.872 0.138 19.896 ;
    END
  END d[71]
  PIN d[72]
    DIRECTION INPUT ;
    USE SIGNAL ;
    PORT
      LAYER M4 ;
        RECT  0.054 20.064 0.138 20.088 ;
    END
  END d[72]
  PIN d[73]
    DIRECTION INPUT ;
    USE SIGNAL ;
    PORT
      LAYER M4 ;
        RECT  0.054 20.256 0.138 20.28 ;
    END
  END d[73]
  PIN d[74]
    DIRECTION INPUT ;
    USE SIGNAL ;
    PORT
      LAYER M4 ;
        RECT  0.054 20.448 0.138 20.472 ;
    END
  END d[74]
  PIN d[75]
    DIRECTION INPUT ;
    USE SIGNAL ;
    PORT
      LAYER M4 ;
        RECT  0.054 20.688 0.138 20.712 ;
    END
  END d[75]
  PIN d[76]
    DIRECTION INPUT ;
    USE SIGNAL ;
    PORT
      LAYER M4 ;
        RECT  0.054 20.88 0.138 20.904 ;
    END
  END d[76]
  PIN d[77]
    DIRECTION INPUT ;
    USE SIGNAL ;
    PORT
      LAYER M4 ;
        RECT  0.054 21.072 0.138 21.096 ;
    END
  END d[77]
  PIN d[78]
    DIRECTION INPUT ;
    USE SIGNAL ;
    PORT
      LAYER M4 ;
        RECT  0.054 21.264 0.138 21.288 ;
    END
  END d[78]
  PIN d[79]
    DIRECTION INPUT ;
    USE SIGNAL ;
    PORT
      LAYER M4 ;
        RECT  0.054 21.504 0.138 21.528 ;
    END
  END d[79]
  PIN d[7]
    DIRECTION INPUT ;
    USE SIGNAL ;
    PORT
      LAYER M4 ;
        RECT  0.054 6.816 0.138 6.84 ;
    END
  END d[7]
  PIN d[80]
    DIRECTION INPUT ;
    USE SIGNAL ;
    PORT
      LAYER M4 ;
        RECT  0.054 21.696 0.138 21.72 ;
    END
  END d[80]
  PIN d[81]
    DIRECTION INPUT ;
    USE SIGNAL ;
    PORT
      LAYER M4 ;
        RECT  0.054 21.888 0.138 21.912 ;
    END
  END d[81]
  PIN d[82]
    DIRECTION INPUT ;
    USE SIGNAL ;
    PORT
      LAYER M4 ;
        RECT  0.054 22.08 0.138 22.104 ;
    END
  END d[82]
  PIN d[83]
    DIRECTION INPUT ;
    USE SIGNAL ;
    PORT
      LAYER M4 ;
        RECT  0.054 22.32 0.138 22.344 ;
    END
  END d[83]
  PIN d[84]
    DIRECTION INPUT ;
    USE SIGNAL ;
    PORT
      LAYER M4 ;
        RECT  0.054 22.512 0.138 22.536 ;
    END
  END d[84]
  PIN d[85]
    DIRECTION INPUT ;
    USE SIGNAL ;
    PORT
      LAYER M4 ;
        RECT  0.054 22.704 0.138 22.728 ;
    END
  END d[85]
  PIN d[86]
    DIRECTION INPUT ;
    USE SIGNAL ;
    PORT
      LAYER M4 ;
        RECT  0.054 22.896 0.138 22.92 ;
    END
  END d[86]
  PIN d[87]
    DIRECTION INPUT ;
    USE SIGNAL ;
    PORT
      LAYER M4 ;
        RECT  0.054 23.136 0.138 23.16 ;
    END
  END d[87]
  PIN d[88]
    DIRECTION INPUT ;
    USE SIGNAL ;
    PORT
      LAYER M4 ;
        RECT  0.054 23.328 0.138 23.352 ;
    END
  END d[88]
  PIN d[89]
    DIRECTION INPUT ;
    USE SIGNAL ;
    PORT
      LAYER M4 ;
        RECT  0.054 23.52 0.138 23.544 ;
    END
  END d[89]
  PIN d[8]
    DIRECTION INPUT ;
    USE SIGNAL ;
    PORT
      LAYER M4 ;
        RECT  0.054 7.008 0.138 7.032 ;
    END
  END d[8]
  PIN d[90]
    DIRECTION INPUT ;
    USE SIGNAL ;
    PORT
      LAYER M4 ;
        RECT  0.054 23.712 0.138 23.736 ;
    END
  END d[90]
  PIN d[91]
    DIRECTION INPUT ;
    USE SIGNAL ;
    PORT
      LAYER M4 ;
        RECT  0.054 23.952 0.138 23.976 ;
    END
  END d[91]
  PIN d[92]
    DIRECTION INPUT ;
    USE SIGNAL ;
    PORT
      LAYER M4 ;
        RECT  0.054 24.144 0.138 24.168 ;
    END
  END d[92]
  PIN d[93]
    DIRECTION INPUT ;
    USE SIGNAL ;
    PORT
      LAYER M4 ;
        RECT  0.054 24.336 0.138 24.36 ;
    END
  END d[93]
  PIN d[94]
    DIRECTION INPUT ;
    USE SIGNAL ;
    PORT
      LAYER M4 ;
        RECT  0.054 24.528 0.138 24.552 ;
    END
  END d[94]
  PIN d[95]
    DIRECTION INPUT ;
    USE SIGNAL ;
    PORT
      LAYER M4 ;
        RECT  0.054 24.768 0.138 24.792 ;
    END
  END d[95]
  PIN d[96]
    DIRECTION INPUT ;
    USE SIGNAL ;
    PORT
      LAYER M4 ;
        RECT  0.054 24.96 0.138 24.984 ;
    END
  END d[96]
  PIN d[97]
    DIRECTION INPUT ;
    USE SIGNAL ;
    PORT
      LAYER M4 ;
        RECT  0.054 25.152 0.138 25.176 ;
    END
  END d[97]
  PIN d[98]
    DIRECTION INPUT ;
    USE SIGNAL ;
    PORT
      LAYER M4 ;
        RECT  0.054 25.344 0.138 25.368 ;
    END
  END d[98]
  PIN d[99]
    DIRECTION INPUT ;
    USE SIGNAL ;
    PORT
      LAYER M4 ;
        RECT  0.054 25.584 0.138 25.608 ;
    END
  END d[99]
  PIN d[9]
    DIRECTION INPUT ;
    USE SIGNAL ;
    PORT
      LAYER M4 ;
        RECT  0.054 7.2 0.138 7.224 ;
    END
  END d[9]
  PIN q[0]
    DIRECTION OUTPUT ;
    USE SIGNAL ;
    PORT
      LAYER M4 ;
        RECT  14.982 5.424 15.066 5.448 ;
    END
  END q[0]
  PIN q[100]
    DIRECTION OUTPUT ;
    USE SIGNAL ;
    PORT
      LAYER M4 ;
        RECT  14.982 32.784 15.066 32.808 ;
    END
  END q[100]
  PIN q[101]
    DIRECTION OUTPUT ;
    USE SIGNAL ;
    PORT
      LAYER M4 ;
        RECT  14.982 33.072 15.066 33.096 ;
    END
  END q[101]
  PIN q[102]
    DIRECTION OUTPUT ;
    USE SIGNAL ;
    PORT
      LAYER M4 ;
        RECT  14.982 33.36 15.066 33.384 ;
    END
  END q[102]
  PIN q[103]
    DIRECTION OUTPUT ;
    USE SIGNAL ;
    PORT
      LAYER M4 ;
        RECT  14.982 33.6 15.066 33.624 ;
    END
  END q[103]
  PIN q[104]
    DIRECTION OUTPUT ;
    USE SIGNAL ;
    PORT
      LAYER M4 ;
        RECT  14.982 33.888 15.066 33.912 ;
    END
  END q[104]
  PIN q[105]
    DIRECTION OUTPUT ;
    USE SIGNAL ;
    PORT
      LAYER M4 ;
        RECT  14.982 34.176 15.066 34.2 ;
    END
  END q[105]
  PIN q[106]
    DIRECTION OUTPUT ;
    USE SIGNAL ;
    PORT
      LAYER M4 ;
        RECT  14.982 34.464 15.066 34.488 ;
    END
  END q[106]
  PIN q[107]
    DIRECTION OUTPUT ;
    USE SIGNAL ;
    PORT
      LAYER M4 ;
        RECT  14.982 34.704 15.066 34.728 ;
    END
  END q[107]
  PIN q[108]
    DIRECTION OUTPUT ;
    USE SIGNAL ;
    PORT
      LAYER M4 ;
        RECT  14.982 34.992 15.066 35.016 ;
    END
  END q[108]
  PIN q[109]
    DIRECTION OUTPUT ;
    USE SIGNAL ;
    PORT
      LAYER M4 ;
        RECT  14.982 35.28 15.066 35.304 ;
    END
  END q[109]
  PIN q[10]
    DIRECTION OUTPUT ;
    USE SIGNAL ;
    PORT
      LAYER M4 ;
        RECT  14.982 8.112 15.066 8.136 ;
    END
  END q[10]
  PIN q[110]
    DIRECTION OUTPUT ;
    USE SIGNAL ;
    PORT
      LAYER M4 ;
        RECT  14.982 35.52 15.066 35.544 ;
    END
  END q[110]
  PIN q[111]
    DIRECTION OUTPUT ;
    USE SIGNAL ;
    PORT
      LAYER M4 ;
        RECT  14.982 35.808 15.066 35.832 ;
    END
  END q[111]
  PIN q[112]
    DIRECTION OUTPUT ;
    USE SIGNAL ;
    PORT
      LAYER M4 ;
        RECT  14.982 36.096 15.066 36.12 ;
    END
  END q[112]
  PIN q[113]
    DIRECTION OUTPUT ;
    USE SIGNAL ;
    PORT
      LAYER M4 ;
        RECT  14.982 36.384 15.066 36.408 ;
    END
  END q[113]
  PIN q[114]
    DIRECTION OUTPUT ;
    USE SIGNAL ;
    PORT
      LAYER M4 ;
        RECT  14.982 36.624 15.066 36.648 ;
    END
  END q[114]
  PIN q[115]
    DIRECTION OUTPUT ;
    USE SIGNAL ;
    PORT
      LAYER M4 ;
        RECT  14.982 36.912 15.066 36.936 ;
    END
  END q[115]
  PIN q[116]
    DIRECTION OUTPUT ;
    USE SIGNAL ;
    PORT
      LAYER M4 ;
        RECT  14.982 37.2 15.066 37.224 ;
    END
  END q[116]
  PIN q[117]
    DIRECTION OUTPUT ;
    USE SIGNAL ;
    PORT
      LAYER M4 ;
        RECT  14.982 37.44 15.066 37.464 ;
    END
  END q[117]
  PIN q[118]
    DIRECTION OUTPUT ;
    USE SIGNAL ;
    PORT
      LAYER M4 ;
        RECT  14.982 37.728 15.066 37.752 ;
    END
  END q[118]
  PIN q[119]
    DIRECTION OUTPUT ;
    USE SIGNAL ;
    PORT
      LAYER M4 ;
        RECT  14.982 38.016 15.066 38.04 ;
    END
  END q[119]
  PIN q[11]
    DIRECTION OUTPUT ;
    USE SIGNAL ;
    PORT
      LAYER M4 ;
        RECT  14.982 8.4 15.066 8.424 ;
    END
  END q[11]
  PIN q[120]
    DIRECTION OUTPUT ;
    USE SIGNAL ;
    PORT
      LAYER M4 ;
        RECT  14.982 38.304 15.066 38.328 ;
    END
  END q[120]
  PIN q[121]
    DIRECTION OUTPUT ;
    USE SIGNAL ;
    PORT
      LAYER M4 ;
        RECT  14.982 38.544 15.066 38.568 ;
    END
  END q[121]
  PIN q[122]
    DIRECTION OUTPUT ;
    USE SIGNAL ;
    PORT
      LAYER M4 ;
        RECT  14.982 38.832 15.066 38.856 ;
    END
  END q[122]
  PIN q[123]
    DIRECTION OUTPUT ;
    USE SIGNAL ;
    PORT
      LAYER M4 ;
        RECT  14.982 39.12 15.066 39.144 ;
    END
  END q[123]
  PIN q[124]
    DIRECTION OUTPUT ;
    USE SIGNAL ;
    PORT
      LAYER M4 ;
        RECT  14.982 39.36 15.066 39.384 ;
    END
  END q[124]
  PIN q[125]
    DIRECTION OUTPUT ;
    USE SIGNAL ;
    PORT
      LAYER M4 ;
        RECT  14.982 39.648 15.066 39.672 ;
    END
  END q[125]
  PIN q[126]
    DIRECTION OUTPUT ;
    USE SIGNAL ;
    PORT
      LAYER M4 ;
        RECT  14.982 39.936 15.066 39.96 ;
    END
  END q[126]
  PIN q[127]
    DIRECTION OUTPUT ;
    USE SIGNAL ;
    PORT
      LAYER M4 ;
        RECT  14.982 40.224 15.066 40.248 ;
    END
  END q[127]
  PIN q[128]
    DIRECTION OUTPUT ;
    USE SIGNAL ;
    PORT
      LAYER M4 ;
        RECT  14.982 40.464 15.066 40.488 ;
    END
  END q[128]
  PIN q[129]
    DIRECTION OUTPUT ;
    USE SIGNAL ;
    PORT
      LAYER M4 ;
        RECT  14.982 40.752 15.066 40.776 ;
    END
  END q[129]
  PIN q[12]
    DIRECTION OUTPUT ;
    USE SIGNAL ;
    PORT
      LAYER M4 ;
        RECT  14.982 8.688 15.066 8.712 ;
    END
  END q[12]
  PIN q[130]
    DIRECTION OUTPUT ;
    USE SIGNAL ;
    PORT
      LAYER M4 ;
        RECT  14.982 41.04 15.066 41.064 ;
    END
  END q[130]
  PIN q[131]
    DIRECTION OUTPUT ;
    USE SIGNAL ;
    PORT
      LAYER M4 ;
        RECT  14.982 41.28 15.066 41.304 ;
    END
  END q[131]
  PIN q[132]
    DIRECTION OUTPUT ;
    USE SIGNAL ;
    PORT
      LAYER M4 ;
        RECT  14.982 41.568 15.066 41.592 ;
    END
  END q[132]
  PIN q[133]
    DIRECTION OUTPUT ;
    USE SIGNAL ;
    PORT
      LAYER M4 ;
        RECT  14.982 41.856 15.066 41.88 ;
    END
  END q[133]
  PIN q[134]
    DIRECTION OUTPUT ;
    USE SIGNAL ;
    PORT
      LAYER M4 ;
        RECT  14.982 42.096 15.066 42.12 ;
    END
  END q[134]
  PIN q[135]
    DIRECTION OUTPUT ;
    USE SIGNAL ;
    PORT
      LAYER M4 ;
        RECT  14.982 42.384 15.066 42.408 ;
    END
  END q[135]
  PIN q[136]
    DIRECTION OUTPUT ;
    USE SIGNAL ;
    PORT
      LAYER M4 ;
        RECT  14.982 42.672 15.066 42.696 ;
    END
  END q[136]
  PIN q[137]
    DIRECTION OUTPUT ;
    USE SIGNAL ;
    PORT
      LAYER M4 ;
        RECT  14.982 42.96 15.066 42.984 ;
    END
  END q[137]
  PIN q[138]
    DIRECTION OUTPUT ;
    USE SIGNAL ;
    PORT
      LAYER M4 ;
        RECT  14.982 43.2 15.066 43.224 ;
    END
  END q[138]
  PIN q[139]
    DIRECTION OUTPUT ;
    USE SIGNAL ;
    PORT
      LAYER M4 ;
        RECT  14.982 43.488 15.066 43.512 ;
    END
  END q[139]
  PIN q[13]
    DIRECTION OUTPUT ;
    USE SIGNAL ;
    PORT
      LAYER M4 ;
        RECT  14.982 8.928 15.066 8.952 ;
    END
  END q[13]
  PIN q[140]
    DIRECTION OUTPUT ;
    USE SIGNAL ;
    PORT
      LAYER M4 ;
        RECT  14.982 43.776 15.066 43.8 ;
    END
  END q[140]
  PIN q[141]
    DIRECTION OUTPUT ;
    USE SIGNAL ;
    PORT
      LAYER M4 ;
        RECT  14.982 44.016 15.066 44.04 ;
    END
  END q[141]
  PIN q[142]
    DIRECTION OUTPUT ;
    USE SIGNAL ;
    PORT
      LAYER M4 ;
        RECT  14.982 44.304 15.066 44.328 ;
    END
  END q[142]
  PIN q[143]
    DIRECTION OUTPUT ;
    USE SIGNAL ;
    PORT
      LAYER M4 ;
        RECT  14.982 44.592 15.066 44.616 ;
    END
  END q[143]
  PIN q[144]
    DIRECTION OUTPUT ;
    USE SIGNAL ;
    PORT
      LAYER M4 ;
        RECT  14.982 44.88 15.066 44.904 ;
    END
  END q[144]
  PIN q[145]
    DIRECTION OUTPUT ;
    USE SIGNAL ;
    PORT
      LAYER M4 ;
        RECT  14.982 45.12 15.066 45.144 ;
    END
  END q[145]
  PIN q[146]
    DIRECTION OUTPUT ;
    USE SIGNAL ;
    PORT
      LAYER M4 ;
        RECT  14.982 45.408 15.066 45.432 ;
    END
  END q[146]
  PIN q[147]
    DIRECTION OUTPUT ;
    USE SIGNAL ;
    PORT
      LAYER M4 ;
        RECT  14.982 45.696 15.066 45.72 ;
    END
  END q[147]
  PIN q[148]
    DIRECTION OUTPUT ;
    USE SIGNAL ;
    PORT
      LAYER M4 ;
        RECT  14.982 45.936 15.066 45.96 ;
    END
  END q[148]
  PIN q[149]
    DIRECTION OUTPUT ;
    USE SIGNAL ;
    PORT
      LAYER M4 ;
        RECT  14.982 46.224 15.066 46.248 ;
    END
  END q[149]
  PIN q[14]
    DIRECTION OUTPUT ;
    USE SIGNAL ;
    PORT
      LAYER M4 ;
        RECT  14.982 9.216 15.066 9.24 ;
    END
  END q[14]
  PIN q[150]
    DIRECTION OUTPUT ;
    USE SIGNAL ;
    PORT
      LAYER M4 ;
        RECT  14.982 46.512 15.066 46.536 ;
    END
  END q[150]
  PIN q[151]
    DIRECTION OUTPUT ;
    USE SIGNAL ;
    PORT
      LAYER M4 ;
        RECT  14.982 46.8 15.066 46.824 ;
    END
  END q[151]
  PIN q[152]
    DIRECTION OUTPUT ;
    USE SIGNAL ;
    PORT
      LAYER M4 ;
        RECT  14.982 47.04 15.066 47.064 ;
    END
  END q[152]
  PIN q[153]
    DIRECTION OUTPUT ;
    USE SIGNAL ;
    PORT
      LAYER M4 ;
        RECT  14.982 47.328 15.066 47.352 ;
    END
  END q[153]
  PIN q[154]
    DIRECTION OUTPUT ;
    USE SIGNAL ;
    PORT
      LAYER M4 ;
        RECT  14.982 47.616 15.066 47.64 ;
    END
  END q[154]
  PIN q[155]
    DIRECTION OUTPUT ;
    USE SIGNAL ;
    PORT
      LAYER M4 ;
        RECT  14.982 47.856 15.066 47.88 ;
    END
  END q[155]
  PIN q[156]
    DIRECTION OUTPUT ;
    USE SIGNAL ;
    PORT
      LAYER M4 ;
        RECT  14.982 48.144 15.066 48.168 ;
    END
  END q[156]
  PIN q[157]
    DIRECTION OUTPUT ;
    USE SIGNAL ;
    PORT
      LAYER M4 ;
        RECT  14.982 48.432 15.066 48.456 ;
    END
  END q[157]
  PIN q[158]
    DIRECTION OUTPUT ;
    USE SIGNAL ;
    PORT
      LAYER M4 ;
        RECT  14.982 48.72 15.066 48.744 ;
    END
  END q[158]
  PIN q[159]
    DIRECTION OUTPUT ;
    USE SIGNAL ;
    PORT
      LAYER M4 ;
        RECT  14.982 48.96 15.066 48.984 ;
    END
  END q[159]
  PIN q[15]
    DIRECTION OUTPUT ;
    USE SIGNAL ;
    PORT
      LAYER M4 ;
        RECT  14.982 9.504 15.066 9.528 ;
    END
  END q[15]
  PIN q[160]
    DIRECTION OUTPUT ;
    USE SIGNAL ;
    PORT
      LAYER M4 ;
        RECT  14.982 49.248 15.066 49.272 ;
    END
  END q[160]
  PIN q[161]
    DIRECTION OUTPUT ;
    USE SIGNAL ;
    PORT
      LAYER M4 ;
        RECT  14.982 49.536 15.066 49.56 ;
    END
  END q[161]
  PIN q[162]
    DIRECTION OUTPUT ;
    USE SIGNAL ;
    PORT
      LAYER M4 ;
        RECT  14.982 49.776 15.066 49.8 ;
    END
  END q[162]
  PIN q[163]
    DIRECTION OUTPUT ;
    USE SIGNAL ;
    PORT
      LAYER M4 ;
        RECT  14.982 50.064 15.066 50.088 ;
    END
  END q[163]
  PIN q[164]
    DIRECTION OUTPUT ;
    USE SIGNAL ;
    PORT
      LAYER M4 ;
        RECT  14.982 50.352 15.066 50.376 ;
    END
  END q[164]
  PIN q[165]
    DIRECTION OUTPUT ;
    USE SIGNAL ;
    PORT
      LAYER M4 ;
        RECT  14.982 50.64 15.066 50.664 ;
    END
  END q[165]
  PIN q[166]
    DIRECTION OUTPUT ;
    USE SIGNAL ;
    PORT
      LAYER M4 ;
        RECT  14.982 50.88 15.066 50.904 ;
    END
  END q[166]
  PIN q[167]
    DIRECTION OUTPUT ;
    USE SIGNAL ;
    PORT
      LAYER M4 ;
        RECT  14.982 51.168 15.066 51.192 ;
    END
  END q[167]
  PIN q[168]
    DIRECTION OUTPUT ;
    USE SIGNAL ;
    PORT
      LAYER M4 ;
        RECT  14.982 51.456 15.066 51.48 ;
    END
  END q[168]
  PIN q[169]
    DIRECTION OUTPUT ;
    USE SIGNAL ;
    PORT
      LAYER M4 ;
        RECT  14.982 51.696 15.066 51.72 ;
    END
  END q[169]
  PIN q[16]
    DIRECTION OUTPUT ;
    USE SIGNAL ;
    PORT
      LAYER M4 ;
        RECT  14.982 9.792 15.066 9.816 ;
    END
  END q[16]
  PIN q[170]
    DIRECTION OUTPUT ;
    USE SIGNAL ;
    PORT
      LAYER M4 ;
        RECT  14.982 51.984 15.066 52.008 ;
    END
  END q[170]
  PIN q[171]
    DIRECTION OUTPUT ;
    USE SIGNAL ;
    PORT
      LAYER M4 ;
        RECT  14.982 52.272 15.066 52.296 ;
    END
  END q[171]
  PIN q[172]
    DIRECTION OUTPUT ;
    USE SIGNAL ;
    PORT
      LAYER M4 ;
        RECT  14.982 52.512 15.066 52.536 ;
    END
  END q[172]
  PIN q[173]
    DIRECTION OUTPUT ;
    USE SIGNAL ;
    PORT
      LAYER M4 ;
        RECT  14.982 52.8 15.066 52.824 ;
    END
  END q[173]
  PIN q[174]
    DIRECTION OUTPUT ;
    USE SIGNAL ;
    PORT
      LAYER M4 ;
        RECT  14.982 53.088 15.066 53.112 ;
    END
  END q[174]
  PIN q[175]
    DIRECTION OUTPUT ;
    USE SIGNAL ;
    PORT
      LAYER M4 ;
        RECT  14.982 53.376 15.066 53.4 ;
    END
  END q[175]
  PIN q[176]
    DIRECTION OUTPUT ;
    USE SIGNAL ;
    PORT
      LAYER M4 ;
        RECT  14.982 53.616 15.066 53.64 ;
    END
  END q[176]
  PIN q[177]
    DIRECTION OUTPUT ;
    USE SIGNAL ;
    PORT
      LAYER M4 ;
        RECT  14.982 53.904 15.066 53.928 ;
    END
  END q[177]
  PIN q[178]
    DIRECTION OUTPUT ;
    USE SIGNAL ;
    PORT
      LAYER M4 ;
        RECT  14.982 54.192 15.066 54.216 ;
    END
  END q[178]
  PIN q[179]
    DIRECTION OUTPUT ;
    USE SIGNAL ;
    PORT
      LAYER M4 ;
        RECT  14.982 54.432 15.066 54.456 ;
    END
  END q[179]
  PIN q[17]
    DIRECTION OUTPUT ;
    USE SIGNAL ;
    PORT
      LAYER M4 ;
        RECT  14.982 10.032 15.066 10.056 ;
    END
  END q[17]
  PIN q[180]
    DIRECTION OUTPUT ;
    USE SIGNAL ;
    PORT
      LAYER M4 ;
        RECT  14.982 54.72 15.066 54.744 ;
    END
  END q[180]
  PIN q[181]
    DIRECTION OUTPUT ;
    USE SIGNAL ;
    PORT
      LAYER M4 ;
        RECT  14.982 55.008 15.066 55.032 ;
    END
  END q[181]
  PIN q[182]
    DIRECTION OUTPUT ;
    USE SIGNAL ;
    PORT
      LAYER M4 ;
        RECT  14.982 55.296 15.066 55.32 ;
    END
  END q[182]
  PIN q[183]
    DIRECTION OUTPUT ;
    USE SIGNAL ;
    PORT
      LAYER M4 ;
        RECT  14.982 55.536 15.066 55.56 ;
    END
  END q[183]
  PIN q[184]
    DIRECTION OUTPUT ;
    USE SIGNAL ;
    PORT
      LAYER M4 ;
        RECT  14.982 55.824 15.066 55.848 ;
    END
  END q[184]
  PIN q[185]
    DIRECTION OUTPUT ;
    USE SIGNAL ;
    PORT
      LAYER M4 ;
        RECT  14.982 56.112 15.066 56.136 ;
    END
  END q[185]
  PIN q[186]
    DIRECTION OUTPUT ;
    USE SIGNAL ;
    PORT
      LAYER M4 ;
        RECT  14.982 56.352 15.066 56.376 ;
    END
  END q[186]
  PIN q[187]
    DIRECTION OUTPUT ;
    USE SIGNAL ;
    PORT
      LAYER M4 ;
        RECT  14.982 56.64 15.066 56.664 ;
    END
  END q[187]
  PIN q[188]
    DIRECTION OUTPUT ;
    USE SIGNAL ;
    PORT
      LAYER M4 ;
        RECT  14.982 56.928 15.066 56.952 ;
    END
  END q[188]
  PIN q[189]
    DIRECTION OUTPUT ;
    USE SIGNAL ;
    PORT
      LAYER M4 ;
        RECT  14.982 57.216 15.066 57.24 ;
    END
  END q[189]
  PIN q[18]
    DIRECTION OUTPUT ;
    USE SIGNAL ;
    PORT
      LAYER M4 ;
        RECT  14.982 10.32 15.066 10.344 ;
    END
  END q[18]
  PIN q[190]
    DIRECTION OUTPUT ;
    USE SIGNAL ;
    PORT
      LAYER M4 ;
        RECT  14.982 57.456 15.066 57.48 ;
    END
  END q[190]
  PIN q[191]
    DIRECTION OUTPUT ;
    USE SIGNAL ;
    PORT
      LAYER M4 ;
        RECT  14.982 57.744 15.066 57.768 ;
    END
  END q[191]
  PIN q[192]
    DIRECTION OUTPUT ;
    USE SIGNAL ;
    PORT
      LAYER M4 ;
        RECT  14.982 58.032 15.066 58.056 ;
    END
  END q[192]
  PIN q[193]
    DIRECTION OUTPUT ;
    USE SIGNAL ;
    PORT
      LAYER M4 ;
        RECT  14.982 58.272 15.066 58.296 ;
    END
  END q[193]
  PIN q[194]
    DIRECTION OUTPUT ;
    USE SIGNAL ;
    PORT
      LAYER M4 ;
        RECT  14.982 58.56 15.066 58.584 ;
    END
  END q[194]
  PIN q[195]
    DIRECTION OUTPUT ;
    USE SIGNAL ;
    PORT
      LAYER M4 ;
        RECT  14.982 58.848 15.066 58.872 ;
    END
  END q[195]
  PIN q[196]
    DIRECTION OUTPUT ;
    USE SIGNAL ;
    PORT
      LAYER M4 ;
        RECT  14.982 59.136 15.066 59.16 ;
    END
  END q[196]
  PIN q[197]
    DIRECTION OUTPUT ;
    USE SIGNAL ;
    PORT
      LAYER M4 ;
        RECT  14.982 59.376 15.066 59.4 ;
    END
  END q[197]
  PIN q[19]
    DIRECTION OUTPUT ;
    USE SIGNAL ;
    PORT
      LAYER M4 ;
        RECT  14.982 10.608 15.066 10.632 ;
    END
  END q[19]
  PIN q[1]
    DIRECTION OUTPUT ;
    USE SIGNAL ;
    PORT
      LAYER M4 ;
        RECT  14.982 5.664 15.066 5.688 ;
    END
  END q[1]
  PIN q[20]
    DIRECTION OUTPUT ;
    USE SIGNAL ;
    PORT
      LAYER M4 ;
        RECT  14.982 10.848 15.066 10.872 ;
    END
  END q[20]
  PIN q[21]
    DIRECTION OUTPUT ;
    USE SIGNAL ;
    PORT
      LAYER M4 ;
        RECT  14.982 11.136 15.066 11.16 ;
    END
  END q[21]
  PIN q[22]
    DIRECTION OUTPUT ;
    USE SIGNAL ;
    PORT
      LAYER M4 ;
        RECT  14.982 11.424 15.066 11.448 ;
    END
  END q[22]
  PIN q[23]
    DIRECTION OUTPUT ;
    USE SIGNAL ;
    PORT
      LAYER M4 ;
        RECT  14.982 11.712 15.066 11.736 ;
    END
  END q[23]
  PIN q[24]
    DIRECTION OUTPUT ;
    USE SIGNAL ;
    PORT
      LAYER M4 ;
        RECT  14.982 11.952 15.066 11.976 ;
    END
  END q[24]
  PIN q[25]
    DIRECTION OUTPUT ;
    USE SIGNAL ;
    PORT
      LAYER M4 ;
        RECT  14.982 12.24 15.066 12.264 ;
    END
  END q[25]
  PIN q[26]
    DIRECTION OUTPUT ;
    USE SIGNAL ;
    PORT
      LAYER M4 ;
        RECT  14.982 12.528 15.066 12.552 ;
    END
  END q[26]
  PIN q[27]
    DIRECTION OUTPUT ;
    USE SIGNAL ;
    PORT
      LAYER M4 ;
        RECT  14.982 12.768 15.066 12.792 ;
    END
  END q[27]
  PIN q[28]
    DIRECTION OUTPUT ;
    USE SIGNAL ;
    PORT
      LAYER M4 ;
        RECT  14.982 13.056 15.066 13.08 ;
    END
  END q[28]
  PIN q[29]
    DIRECTION OUTPUT ;
    USE SIGNAL ;
    PORT
      LAYER M4 ;
        RECT  14.982 13.344 15.066 13.368 ;
    END
  END q[29]
  PIN q[2]
    DIRECTION OUTPUT ;
    USE SIGNAL ;
    PORT
      LAYER M4 ;
        RECT  14.982 5.952 15.066 5.976 ;
    END
  END q[2]
  PIN q[30]
    DIRECTION OUTPUT ;
    USE SIGNAL ;
    PORT
      LAYER M4 ;
        RECT  14.982 13.632 15.066 13.656 ;
    END
  END q[30]
  PIN q[31]
    DIRECTION OUTPUT ;
    USE SIGNAL ;
    PORT
      LAYER M4 ;
        RECT  14.982 13.872 15.066 13.896 ;
    END
  END q[31]
  PIN q[32]
    DIRECTION OUTPUT ;
    USE SIGNAL ;
    PORT
      LAYER M4 ;
        RECT  14.982 14.16 15.066 14.184 ;
    END
  END q[32]
  PIN q[33]
    DIRECTION OUTPUT ;
    USE SIGNAL ;
    PORT
      LAYER M4 ;
        RECT  14.982 14.448 15.066 14.472 ;
    END
  END q[33]
  PIN q[34]
    DIRECTION OUTPUT ;
    USE SIGNAL ;
    PORT
      LAYER M4 ;
        RECT  14.982 14.688 15.066 14.712 ;
    END
  END q[34]
  PIN q[35]
    DIRECTION OUTPUT ;
    USE SIGNAL ;
    PORT
      LAYER M4 ;
        RECT  14.982 14.976 15.066 15 ;
    END
  END q[35]
  PIN q[36]
    DIRECTION OUTPUT ;
    USE SIGNAL ;
    PORT
      LAYER M4 ;
        RECT  14.982 15.264 15.066 15.288 ;
    END
  END q[36]
  PIN q[37]
    DIRECTION OUTPUT ;
    USE SIGNAL ;
    PORT
      LAYER M4 ;
        RECT  14.982 15.552 15.066 15.576 ;
    END
  END q[37]
  PIN q[38]
    DIRECTION OUTPUT ;
    USE SIGNAL ;
    PORT
      LAYER M4 ;
        RECT  14.982 15.792 15.066 15.816 ;
    END
  END q[38]
  PIN q[39]
    DIRECTION OUTPUT ;
    USE SIGNAL ;
    PORT
      LAYER M4 ;
        RECT  14.982 16.08 15.066 16.104 ;
    END
  END q[39]
  PIN q[3]
    DIRECTION OUTPUT ;
    USE SIGNAL ;
    PORT
      LAYER M4 ;
        RECT  14.982 6.192 15.066 6.216 ;
    END
  END q[3]
  PIN q[40]
    DIRECTION OUTPUT ;
    USE SIGNAL ;
    PORT
      LAYER M4 ;
        RECT  14.982 16.368 15.066 16.392 ;
    END
  END q[40]
  PIN q[41]
    DIRECTION OUTPUT ;
    USE SIGNAL ;
    PORT
      LAYER M4 ;
        RECT  14.982 16.608 15.066 16.632 ;
    END
  END q[41]
  PIN q[42]
    DIRECTION OUTPUT ;
    USE SIGNAL ;
    PORT
      LAYER M4 ;
        RECT  14.982 16.896 15.066 16.92 ;
    END
  END q[42]
  PIN q[43]
    DIRECTION OUTPUT ;
    USE SIGNAL ;
    PORT
      LAYER M4 ;
        RECT  14.982 17.184 15.066 17.208 ;
    END
  END q[43]
  PIN q[44]
    DIRECTION OUTPUT ;
    USE SIGNAL ;
    PORT
      LAYER M4 ;
        RECT  14.982 17.472 15.066 17.496 ;
    END
  END q[44]
  PIN q[45]
    DIRECTION OUTPUT ;
    USE SIGNAL ;
    PORT
      LAYER M4 ;
        RECT  14.982 17.712 15.066 17.736 ;
    END
  END q[45]
  PIN q[46]
    DIRECTION OUTPUT ;
    USE SIGNAL ;
    PORT
      LAYER M4 ;
        RECT  14.982 18 15.066 18.024 ;
    END
  END q[46]
  PIN q[47]
    DIRECTION OUTPUT ;
    USE SIGNAL ;
    PORT
      LAYER M4 ;
        RECT  14.982 18.288 15.066 18.312 ;
    END
  END q[47]
  PIN q[48]
    DIRECTION OUTPUT ;
    USE SIGNAL ;
    PORT
      LAYER M4 ;
        RECT  14.982 18.528 15.066 18.552 ;
    END
  END q[48]
  PIN q[49]
    DIRECTION OUTPUT ;
    USE SIGNAL ;
    PORT
      LAYER M4 ;
        RECT  14.982 18.816 15.066 18.84 ;
    END
  END q[49]
  PIN q[4]
    DIRECTION OUTPUT ;
    USE SIGNAL ;
    PORT
      LAYER M4 ;
        RECT  14.982 6.48 15.066 6.504 ;
    END
  END q[4]
  PIN q[50]
    DIRECTION OUTPUT ;
    USE SIGNAL ;
    PORT
      LAYER M4 ;
        RECT  14.982 19.104 15.066 19.128 ;
    END
  END q[50]
  PIN q[51]
    DIRECTION OUTPUT ;
    USE SIGNAL ;
    PORT
      LAYER M4 ;
        RECT  14.982 19.344 15.066 19.368 ;
    END
  END q[51]
  PIN q[52]
    DIRECTION OUTPUT ;
    USE SIGNAL ;
    PORT
      LAYER M4 ;
        RECT  14.982 19.632 15.066 19.656 ;
    END
  END q[52]
  PIN q[53]
    DIRECTION OUTPUT ;
    USE SIGNAL ;
    PORT
      LAYER M4 ;
        RECT  14.982 19.92 15.066 19.944 ;
    END
  END q[53]
  PIN q[54]
    DIRECTION OUTPUT ;
    USE SIGNAL ;
    PORT
      LAYER M4 ;
        RECT  14.982 20.208 15.066 20.232 ;
    END
  END q[54]
  PIN q[55]
    DIRECTION OUTPUT ;
    USE SIGNAL ;
    PORT
      LAYER M4 ;
        RECT  14.982 20.448 15.066 20.472 ;
    END
  END q[55]
  PIN q[56]
    DIRECTION OUTPUT ;
    USE SIGNAL ;
    PORT
      LAYER M4 ;
        RECT  14.982 20.736 15.066 20.76 ;
    END
  END q[56]
  PIN q[57]
    DIRECTION OUTPUT ;
    USE SIGNAL ;
    PORT
      LAYER M4 ;
        RECT  14.982 21.024 15.066 21.048 ;
    END
  END q[57]
  PIN q[58]
    DIRECTION OUTPUT ;
    USE SIGNAL ;
    PORT
      LAYER M4 ;
        RECT  14.982 21.264 15.066 21.288 ;
    END
  END q[58]
  PIN q[59]
    DIRECTION OUTPUT ;
    USE SIGNAL ;
    PORT
      LAYER M4 ;
        RECT  14.982 21.552 15.066 21.576 ;
    END
  END q[59]
  PIN q[5]
    DIRECTION OUTPUT ;
    USE SIGNAL ;
    PORT
      LAYER M4 ;
        RECT  14.982 6.768 15.066 6.792 ;
    END
  END q[5]
  PIN q[60]
    DIRECTION OUTPUT ;
    USE SIGNAL ;
    PORT
      LAYER M4 ;
        RECT  14.982 21.84 15.066 21.864 ;
    END
  END q[60]
  PIN q[61]
    DIRECTION OUTPUT ;
    USE SIGNAL ;
    PORT
      LAYER M4 ;
        RECT  14.982 22.128 15.066 22.152 ;
    END
  END q[61]
  PIN q[62]
    DIRECTION OUTPUT ;
    USE SIGNAL ;
    PORT
      LAYER M4 ;
        RECT  14.982 22.368 15.066 22.392 ;
    END
  END q[62]
  PIN q[63]
    DIRECTION OUTPUT ;
    USE SIGNAL ;
    PORT
      LAYER M4 ;
        RECT  14.982 22.656 15.066 22.68 ;
    END
  END q[63]
  PIN q[64]
    DIRECTION OUTPUT ;
    USE SIGNAL ;
    PORT
      LAYER M4 ;
        RECT  14.982 22.944 15.066 22.968 ;
    END
  END q[64]
  PIN q[65]
    DIRECTION OUTPUT ;
    USE SIGNAL ;
    PORT
      LAYER M4 ;
        RECT  14.982 23.184 15.066 23.208 ;
    END
  END q[65]
  PIN q[66]
    DIRECTION OUTPUT ;
    USE SIGNAL ;
    PORT
      LAYER M4 ;
        RECT  14.982 23.472 15.066 23.496 ;
    END
  END q[66]
  PIN q[67]
    DIRECTION OUTPUT ;
    USE SIGNAL ;
    PORT
      LAYER M4 ;
        RECT  14.982 23.76 15.066 23.784 ;
    END
  END q[67]
  PIN q[68]
    DIRECTION OUTPUT ;
    USE SIGNAL ;
    PORT
      LAYER M4 ;
        RECT  14.982 24.048 15.066 24.072 ;
    END
  END q[68]
  PIN q[69]
    DIRECTION OUTPUT ;
    USE SIGNAL ;
    PORT
      LAYER M4 ;
        RECT  14.982 24.288 15.066 24.312 ;
    END
  END q[69]
  PIN q[6]
    DIRECTION OUTPUT ;
    USE SIGNAL ;
    PORT
      LAYER M4 ;
        RECT  14.982 7.056 15.066 7.08 ;
    END
  END q[6]
  PIN q[70]
    DIRECTION OUTPUT ;
    USE SIGNAL ;
    PORT
      LAYER M4 ;
        RECT  14.982 24.576 15.066 24.6 ;
    END
  END q[70]
  PIN q[71]
    DIRECTION OUTPUT ;
    USE SIGNAL ;
    PORT
      LAYER M4 ;
        RECT  14.982 24.864 15.066 24.888 ;
    END
  END q[71]
  PIN q[72]
    DIRECTION OUTPUT ;
    USE SIGNAL ;
    PORT
      LAYER M4 ;
        RECT  14.982 25.104 15.066 25.128 ;
    END
  END q[72]
  PIN q[73]
    DIRECTION OUTPUT ;
    USE SIGNAL ;
    PORT
      LAYER M4 ;
        RECT  14.982 25.392 15.066 25.416 ;
    END
  END q[73]
  PIN q[74]
    DIRECTION OUTPUT ;
    USE SIGNAL ;
    PORT
      LAYER M4 ;
        RECT  14.982 25.68 15.066 25.704 ;
    END
  END q[74]
  PIN q[75]
    DIRECTION OUTPUT ;
    USE SIGNAL ;
    PORT
      LAYER M4 ;
        RECT  14.982 25.968 15.066 25.992 ;
    END
  END q[75]
  PIN q[76]
    DIRECTION OUTPUT ;
    USE SIGNAL ;
    PORT
      LAYER M4 ;
        RECT  14.982 26.208 15.066 26.232 ;
    END
  END q[76]
  PIN q[77]
    DIRECTION OUTPUT ;
    USE SIGNAL ;
    PORT
      LAYER M4 ;
        RECT  14.982 26.496 15.066 26.52 ;
    END
  END q[77]
  PIN q[78]
    DIRECTION OUTPUT ;
    USE SIGNAL ;
    PORT
      LAYER M4 ;
        RECT  14.982 26.784 15.066 26.808 ;
    END
  END q[78]
  PIN q[79]
    DIRECTION OUTPUT ;
    USE SIGNAL ;
    PORT
      LAYER M4 ;
        RECT  14.982 27.024 15.066 27.048 ;
    END
  END q[79]
  PIN q[7]
    DIRECTION OUTPUT ;
    USE SIGNAL ;
    PORT
      LAYER M4 ;
        RECT  14.982 7.296 15.066 7.32 ;
    END
  END q[7]
  PIN q[80]
    DIRECTION OUTPUT ;
    USE SIGNAL ;
    PORT
      LAYER M4 ;
        RECT  14.982 27.312 15.066 27.336 ;
    END
  END q[80]
  PIN q[81]
    DIRECTION OUTPUT ;
    USE SIGNAL ;
    PORT
      LAYER M4 ;
        RECT  14.982 27.6 15.066 27.624 ;
    END
  END q[81]
  PIN q[82]
    DIRECTION OUTPUT ;
    USE SIGNAL ;
    PORT
      LAYER M4 ;
        RECT  14.982 27.888 15.066 27.912 ;
    END
  END q[82]
  PIN q[83]
    DIRECTION OUTPUT ;
    USE SIGNAL ;
    PORT
      LAYER M4 ;
        RECT  14.982 28.128 15.066 28.152 ;
    END
  END q[83]
  PIN q[84]
    DIRECTION OUTPUT ;
    USE SIGNAL ;
    PORT
      LAYER M4 ;
        RECT  14.982 28.416 15.066 28.44 ;
    END
  END q[84]
  PIN q[85]
    DIRECTION OUTPUT ;
    USE SIGNAL ;
    PORT
      LAYER M4 ;
        RECT  14.982 28.704 15.066 28.728 ;
    END
  END q[85]
  PIN q[86]
    DIRECTION OUTPUT ;
    USE SIGNAL ;
    PORT
      LAYER M4 ;
        RECT  14.982 28.944 15.066 28.968 ;
    END
  END q[86]
  PIN q[87]
    DIRECTION OUTPUT ;
    USE SIGNAL ;
    PORT
      LAYER M4 ;
        RECT  14.982 29.232 15.066 29.256 ;
    END
  END q[87]
  PIN q[88]
    DIRECTION OUTPUT ;
    USE SIGNAL ;
    PORT
      LAYER M4 ;
        RECT  14.982 29.52 15.066 29.544 ;
    END
  END q[88]
  PIN q[89]
    DIRECTION OUTPUT ;
    USE SIGNAL ;
    PORT
      LAYER M4 ;
        RECT  14.982 29.76 15.066 29.784 ;
    END
  END q[89]
  PIN q[8]
    DIRECTION OUTPUT ;
    USE SIGNAL ;
    PORT
      LAYER M4 ;
        RECT  14.982 7.584 15.066 7.608 ;
    END
  END q[8]
  PIN q[90]
    DIRECTION OUTPUT ;
    USE SIGNAL ;
    PORT
      LAYER M4 ;
        RECT  14.982 30.048 15.066 30.072 ;
    END
  END q[90]
  PIN q[91]
    DIRECTION OUTPUT ;
    USE SIGNAL ;
    PORT
      LAYER M4 ;
        RECT  14.982 30.336 15.066 30.36 ;
    END
  END q[91]
  PIN q[92]
    DIRECTION OUTPUT ;
    USE SIGNAL ;
    PORT
      LAYER M4 ;
        RECT  14.982 30.624 15.066 30.648 ;
    END
  END q[92]
  PIN q[93]
    DIRECTION OUTPUT ;
    USE SIGNAL ;
    PORT
      LAYER M4 ;
        RECT  14.982 30.864 15.066 30.888 ;
    END
  END q[93]
  PIN q[94]
    DIRECTION OUTPUT ;
    USE SIGNAL ;
    PORT
      LAYER M4 ;
        RECT  14.982 31.152 15.066 31.176 ;
    END
  END q[94]
  PIN q[95]
    DIRECTION OUTPUT ;
    USE SIGNAL ;
    PORT
      LAYER M4 ;
        RECT  14.982 31.44 15.066 31.464 ;
    END
  END q[95]
  PIN q[96]
    DIRECTION OUTPUT ;
    USE SIGNAL ;
    PORT
      LAYER M4 ;
        RECT  14.982 31.68 15.066 31.704 ;
    END
  END q[96]
  PIN q[97]
    DIRECTION OUTPUT ;
    USE SIGNAL ;
    PORT
      LAYER M4 ;
        RECT  14.982 31.968 15.066 31.992 ;
    END
  END q[97]
  PIN q[98]
    DIRECTION OUTPUT ;
    USE SIGNAL ;
    PORT
      LAYER M4 ;
        RECT  14.982 32.256 15.066 32.28 ;
    END
  END q[98]
  PIN q[99]
    DIRECTION OUTPUT ;
    USE SIGNAL ;
    PORT
      LAYER M4 ;
        RECT  14.982 32.544 15.066 32.568 ;
    END
  END q[99]
  PIN q[9]
    DIRECTION OUTPUT ;
    USE SIGNAL ;
    PORT
      LAYER M4 ;
        RECT  14.982 7.872 15.066 7.896 ;
    END
  END q[9]
  PIN rst_n
    DIRECTION INPUT ;
    USE SIGNAL ;
    PORT
      LAYER M5 ;
        RECT  9.696 0.054 9.72 0.138 ;
    END
    PORT
      LAYER M5 ;
        RECT  9.696 0.08 9.72 2.137 ;
    END
  END rst_n
  PIN VDD
    DIRECTION INOUT ;
    USE POWER ;
    PORT
      LAYER M5 ;
        RECT  10.692 2.151 10.812 62.649 ;
        RECT  7.992 2.151 8.112 62.649 ;
        RECT  5.292 2.151 5.412 62.649 ;
        RECT  2.592 2.151 2.712 62.649 ;
    END
  END VDD
  PIN VSS
    DIRECTION INOUT ;
    USE GROUND ;
    PORT
      LAYER M5 ;
        RECT  10.5 2.137 10.62 62.663 ;
        RECT  7.8 2.137 7.92 62.663 ;
        RECT  5.1 2.137 5.22 62.663 ;
        RECT  2.4 2.137 2.52 62.663 ;
    END
  END VSS
  # OT_OBS_CLOSED layer=M5 d_um=1.536 added=20
  OBS
    LAYER RVTN ;
     RECT  2.16 2.16 12.96 2.295 ;
     RECT  2.16 2.565 12.96 2.835 ;
     RECT  2.16 3.105 12.96 3.375 ;
     RECT  2.16 3.645 12.96 3.915 ;
     RECT  2.16 4.185 12.96 4.455 ;
     RECT  2.16 4.725 12.96 4.995 ;
     RECT  2.16 5.265 12.96 5.535 ;
     RECT  2.16 5.805 12.96 6.075 ;
     RECT  2.16 6.345 12.96 6.615 ;
     RECT  2.16 6.885 12.96 7.155 ;
     RECT  2.16 7.425 12.96 7.695 ;
     RECT  2.16 7.965 12.96 8.235 ;
     RECT  2.16 8.505 12.96 8.775 ;
     RECT  2.16 9.045 12.96 9.315 ;
     RECT  2.16 9.585 12.96 9.855 ;
     RECT  2.16 10.125 12.96 10.395 ;
     RECT  2.16 10.665 12.96 10.935 ;
     RECT  2.16 11.205 12.96 11.475 ;
     RECT  2.16 11.745 12.96 12.015 ;
     RECT  2.16 12.285 12.96 12.555 ;
     RECT  2.16 12.825 12.96 13.095 ;
     RECT  2.16 13.365 12.96 13.635 ;
     RECT  2.16 13.905 12.96 14.175 ;
     RECT  2.16 14.445 12.96 14.715 ;
     RECT  2.16 14.985 12.96 15.255 ;
     RECT  2.16 15.525 12.96 15.795 ;
     RECT  2.16 16.065 12.96 16.335 ;
     RECT  2.16 16.605 12.96 16.875 ;
     RECT  2.16 17.145 12.96 17.415 ;
     RECT  2.16 17.685 12.96 17.955 ;
     RECT  2.16 18.225 12.96 18.495 ;
     RECT  2.16 18.765 12.96 19.035 ;
     RECT  2.16 19.305 12.96 19.575 ;
     RECT  2.16 19.845 12.96 20.115 ;
     RECT  2.16 20.385 12.96 20.655 ;
     RECT  2.16 20.925 12.96 21.195 ;
     RECT  2.16 21.465 12.96 21.735 ;
     RECT  2.16 22.005 12.96 22.275 ;
     RECT  2.16 22.545 12.96 22.815 ;
     RECT  2.16 23.085 12.96 23.355 ;
     RECT  2.16 23.625 12.96 23.895 ;
     RECT  2.16 24.165 12.96 24.435 ;
     RECT  2.16 24.705 12.96 24.975 ;
     RECT  2.16 25.245 12.96 25.515 ;
     RECT  2.16 25.785 12.96 26.055 ;
     RECT  2.16 26.325 12.96 26.595 ;
     RECT  2.16 26.865 12.96 27.135 ;
     RECT  2.16 27.405 12.96 27.675 ;
     RECT  2.16 27.945 12.96 28.215 ;
     RECT  2.16 28.485 12.96 28.755 ;
     RECT  2.16 29.025 12.96 29.295 ;
     RECT  2.16 29.565 12.96 29.835 ;
     RECT  2.16 30.105 12.96 30.375 ;
     RECT  2.16 30.645 12.96 30.915 ;
     RECT  2.16 31.185 12.96 31.455 ;
     RECT  2.16 31.725 12.96 31.995 ;
     RECT  2.16 32.265 12.96 32.535 ;
     RECT  2.16 32.805 12.96 33.075 ;
     RECT  2.16 33.345 12.96 33.615 ;
     RECT  2.16 33.885 12.96 34.155 ;
     RECT  2.16 34.425 12.96 34.695 ;
     RECT  2.16 34.965 12.96 35.235 ;
     RECT  2.16 35.505 12.96 35.775 ;
     RECT  2.16 36.045 12.96 36.315 ;
     RECT  2.16 36.585 12.96 36.855 ;
     RECT  2.16 37.125 12.96 37.395 ;
     RECT  2.16 37.665 12.96 37.935 ;
     RECT  2.16 38.205 12.96 38.475 ;
     RECT  2.16 38.745 12.96 39.015 ;
     RECT  2.16 39.285 12.96 39.555 ;
     RECT  2.16 39.825 12.96 40.095 ;
     RECT  2.16 40.365 12.96 40.635 ;
     RECT  2.16 40.905 12.96 41.175 ;
     RECT  2.16 41.445 12.96 41.715 ;
     RECT  2.16 41.985 12.96 42.255 ;
     RECT  2.16 42.525 12.96 42.795 ;
     RECT  2.16 43.065 12.96 43.335 ;
     RECT  2.16 43.605 12.96 43.875 ;
     RECT  2.16 44.145 12.96 44.415 ;
     RECT  2.16 44.685 12.96 44.955 ;
     RECT  2.16 45.225 12.96 45.495 ;
     RECT  2.16 45.765 12.96 46.035 ;
     RECT  2.16 46.305 12.96 46.575 ;
     RECT  2.16 46.845 12.96 47.115 ;
     RECT  2.16 47.385 12.96 47.655 ;
     RECT  2.16 47.925 12.96 48.195 ;
     RECT  2.16 48.465 12.96 48.735 ;
     RECT  2.16 49.005 12.96 49.275 ;
     RECT  2.16 49.545 12.96 49.815 ;
     RECT  2.16 50.085 12.96 50.355 ;
     RECT  2.16 50.625 12.96 50.895 ;
     RECT  2.16 51.165 12.96 51.435 ;
     RECT  2.16 51.705 12.96 51.975 ;
     RECT  2.16 52.245 12.96 52.515 ;
     RECT  2.16 52.785 12.96 53.055 ;
     RECT  2.16 53.325 12.96 53.595 ;
     RECT  2.16 53.865 12.96 54.135 ;
     RECT  2.16 54.405 12.96 54.675 ;
     RECT  2.16 54.945 12.96 55.215 ;
     RECT  2.16 55.485 12.96 55.755 ;
     RECT  2.16 56.025 12.96 56.295 ;
     RECT  2.16 56.565 12.96 56.835 ;
     RECT  2.16 57.105 12.96 57.375 ;
     RECT  2.16 57.645 12.96 57.915 ;
     RECT  2.16 58.185 12.96 58.455 ;
     RECT  2.16 58.725 12.96 58.995 ;
     RECT  2.16 59.265 12.96 59.535 ;
     RECT  2.16 59.805 12.96 60.075 ;
     RECT  2.16 60.345 12.96 60.615 ;
     RECT  2.16 60.885 12.96 61.155 ;
     RECT  2.16 61.425 12.96 61.695 ;
     RECT  2.16 61.965 12.96 62.235 ;
     RECT  2.16 62.505 12.96 62.64 ;
    LAYER RVTP ;
     RECT  2.16 2.295 12.96 2.565 ;
     RECT  2.16 2.835 12.96 3.105 ;
     RECT  2.16 3.375 12.96 3.645 ;
     RECT  2.16 3.915 12.96 4.185 ;
     RECT  2.16 4.455 12.96 4.725 ;
     RECT  2.16 4.995 12.96 5.265 ;
     RECT  2.16 5.535 12.96 5.805 ;
     RECT  2.16 6.075 12.96 6.345 ;
     RECT  2.16 6.615 12.96 6.885 ;
     RECT  2.16 7.155 12.96 7.425 ;
     RECT  2.16 7.695 12.96 7.965 ;
     RECT  2.16 8.235 12.96 8.505 ;
     RECT  2.16 8.775 12.96 9.045 ;
     RECT  2.16 9.315 12.96 9.585 ;
     RECT  2.16 9.855 12.96 10.125 ;
     RECT  2.16 10.395 12.96 10.665 ;
     RECT  2.16 10.935 12.96 11.205 ;
     RECT  2.16 11.475 12.96 11.745 ;
     RECT  2.16 12.015 12.96 12.285 ;
     RECT  2.16 12.555 12.96 12.825 ;
     RECT  2.16 13.095 12.96 13.365 ;
     RECT  2.16 13.635 12.96 13.905 ;
     RECT  2.16 14.175 12.96 14.445 ;
     RECT  2.16 14.715 12.96 14.985 ;
     RECT  2.16 15.255 12.96 15.525 ;
     RECT  2.16 15.795 12.96 16.065 ;
     RECT  2.16 16.335 12.96 16.605 ;
     RECT  2.16 16.875 12.96 17.145 ;
     RECT  2.16 17.415 12.96 17.685 ;
     RECT  2.16 17.955 12.96 18.225 ;
     RECT  2.16 18.495 12.96 18.765 ;
     RECT  2.16 19.035 12.96 19.305 ;
     RECT  2.16 19.575 12.96 19.845 ;
     RECT  2.16 20.115 12.96 20.385 ;
     RECT  2.16 20.655 12.96 20.925 ;
     RECT  2.16 21.195 12.96 21.465 ;
     RECT  2.16 21.735 12.96 22.005 ;
     RECT  2.16 22.275 12.96 22.545 ;
     RECT  2.16 22.815 12.96 23.085 ;
     RECT  2.16 23.355 12.96 23.625 ;
     RECT  2.16 23.895 12.96 24.165 ;
     RECT  2.16 24.435 12.96 24.705 ;
     RECT  2.16 24.975 12.96 25.245 ;
     RECT  2.16 25.515 12.96 25.785 ;
     RECT  2.16 26.055 12.96 26.325 ;
     RECT  2.16 26.595 12.96 26.865 ;
     RECT  2.16 27.135 12.96 27.405 ;
     RECT  2.16 27.675 12.96 27.945 ;
     RECT  2.16 28.215 12.96 28.485 ;
     RECT  2.16 28.755 12.96 29.025 ;
     RECT  2.16 29.295 12.96 29.565 ;
     RECT  2.16 29.835 12.96 30.105 ;
     RECT  2.16 30.375 12.96 30.645 ;
     RECT  2.16 30.915 12.96 31.185 ;
     RECT  2.16 31.455 12.96 31.725 ;
     RECT  2.16 31.995 12.96 32.265 ;
     RECT  2.16 32.535 12.96 32.805 ;
     RECT  2.16 33.075 12.96 33.345 ;
     RECT  2.16 33.615 12.96 33.885 ;
     RECT  2.16 34.155 12.96 34.425 ;
     RECT  2.16 34.695 12.96 34.965 ;
     RECT  2.16 35.235 12.96 35.505 ;
     RECT  2.16 35.775 12.96 36.045 ;
     RECT  2.16 36.315 12.96 36.585 ;
     RECT  2.16 36.855 12.96 37.125 ;
     RECT  2.16 37.395 12.96 37.665 ;
     RECT  2.16 37.935 12.96 38.205 ;
     RECT  2.16 38.475 12.96 38.745 ;
     RECT  2.16 39.015 12.96 39.285 ;
     RECT  2.16 39.555 12.96 39.825 ;
     RECT  2.16 40.095 12.96 40.365 ;
     RECT  2.16 40.635 12.96 40.905 ;
     RECT  2.16 41.175 12.96 41.445 ;
     RECT  2.16 41.715 12.96 41.985 ;
     RECT  2.16 42.255 12.96 42.525 ;
     RECT  2.16 42.795 12.96 43.065 ;
     RECT  2.16 43.335 12.96 43.605 ;
     RECT  2.16 43.875 12.96 44.145 ;
     RECT  2.16 44.415 12.96 44.685 ;
     RECT  2.16 44.955 12.96 45.225 ;
     RECT  2.16 45.495 12.96 45.765 ;
     RECT  2.16 46.035 12.96 46.305 ;
     RECT  2.16 46.575 12.96 46.845 ;
     RECT  2.16 47.115 12.96 47.385 ;
     RECT  2.16 47.655 12.96 47.925 ;
     RECT  2.16 48.195 12.96 48.465 ;
     RECT  2.16 48.735 12.96 49.005 ;
     RECT  2.16 49.275 12.96 49.545 ;
     RECT  2.16 49.815 12.96 50.085 ;
     RECT  2.16 50.355 12.96 50.625 ;
     RECT  2.16 50.895 12.96 51.165 ;
     RECT  2.16 51.435 12.96 51.705 ;
     RECT  2.16 51.975 12.96 52.245 ;
     RECT  2.16 52.515 12.96 52.785 ;
     RECT  2.16 53.055 12.96 53.325 ;
     RECT  2.16 53.595 12.96 53.865 ;
     RECT  2.16 54.135 12.96 54.405 ;
     RECT  2.16 54.675 12.96 54.945 ;
     RECT  2.16 55.215 12.96 55.485 ;
     RECT  2.16 55.755 12.96 56.025 ;
     RECT  2.16 56.295 12.96 56.565 ;
     RECT  2.16 56.835 12.96 57.105 ;
     RECT  2.16 57.375 12.96 57.645 ;
     RECT  2.16 57.915 12.96 58.185 ;
     RECT  2.16 58.455 12.96 58.725 ;
     RECT  2.16 58.995 12.96 59.265 ;
     RECT  2.16 59.535 12.96 59.805 ;
     RECT  2.16 60.075 12.96 60.345 ;
     RECT  2.16 60.615 12.96 60.885 ;
     RECT  2.16 61.155 12.96 61.425 ;
     RECT  2.16 61.695 12.96 61.965 ;
     RECT  2.16 62.235 12.96 62.505 ;
    LAYER M1 ;
     RECT  2.16 2.151 12.96 62.649 ;
    LAYER M2 ;
     RECT  0.031 46.701 0.067 46.836 ;
     RECT  0.031 50.706 0.067 50.724 ;
     RECT  0.103 27.918 0.139 27.936 ;
     RECT  0.031 42.768 0.139 42.786 ;
     RECT  0.067 50.4 0.167 50.724 ;
     RECT  0.031 52.686 0.167 52.704 ;
     RECT  0.139 4.23 0.175 4.248 ;
     RECT  0.139 5.58 0.175 5.598 ;
     RECT  0.139 19.242 0.175 19.368 ;
     RECT  0.067 46.512 0.175 46.836 ;
     RECT  0.175 46.35 0.203 46.836 ;
     RECT  0.175 4.23 0.211 4.518 ;
     RECT  0.203 46.35 0.239 46.674 ;
     RECT  0.139 54.684 0.239 54.702 ;
     RECT  0.211 37.062 0.247 37.08 ;
     RECT  0.283 39.6 0.319 39.618 ;
     RECT  0.139 42.768 0.391 43.326 ;
     RECT  0.355 31.896 0.427 31.914 ;
     RECT  0.239 46.35 0.427 46.602 ;
     RECT  0.139 23.022 0.499 26.28 ;
     RECT  0.391 42.768 0.527 43.668 ;
     RECT  0.167 50.634 0.527 50.724 ;
     RECT  0.427 46.008 0.563 46.602 ;
     RECT  0.175 47.862 0.643 47.88 ;
     RECT  0.643 47.862 0.679 48.456 ;
     RECT  0.535 30.114 0.715 30.132 ;
     RECT  0.535 30.924 0.715 30.942 ;
     RECT  0.751 29.34 0.787 29.358 ;
     RECT  0.679 47.736 0.823 48.456 ;
     RECT  0.175 18.54 0.859 19.368 ;
     RECT  0.787 28.692 0.859 29.358 ;
     RECT  0.715 30.114 0.859 30.942 ;
     RECT  0.823 47.736 0.895 48.996 ;
     RECT  0.139 27.18 0.931 27.936 ;
     RECT  0.859 28.692 0.931 30.942 ;
     RECT  0.895 47.736 0.931 49.572 ;
     RECT  0.139 14.382 1.147 14.4 ;
     RECT  0.499 23.022 1.147 26.388 ;
     RECT  0.931 27.18 1.147 30.942 ;
     RECT  0.427 31.851 1.147 31.914 ;
     RECT  0.067 33.048 1.147 33.066 ;
     RECT  1.147 31.851 1.183 33.066 ;
     RECT  0.463 34.164 1.219 34.182 ;
     RECT  0.175 35.316 1.219 35.334 ;
     RECT  1.147 23.022 1.291 30.942 ;
     RECT  0.319 39.222 1.291 39.618 ;
     RECT  1.147 14.382 1.327 14.859 ;
     RECT  1.291 22.752 1.327 30.942 ;
     RECT  1.183 31.851 1.327 33.138 ;
     RECT  0.527 43.002 1.327 43.668 ;
     RECT  1.327 14.382 1.507 15.048 ;
     RECT  0.247 37.062 1.507 37.62 ;
     RECT  1.507 14.382 1.579 15.552 ;
     RECT  1.219 16.38 1.579 16.398 ;
     RECT  1.219 34.164 1.579 35.334 ;
     RECT  1.327 22.752 1.615 33.138 ;
     RECT  0.175 5.58 1.651 5.868 ;
     RECT  0.211 4.23 1.687 4.788 ;
     RECT  1.651 5.58 1.687 6.408 ;
     RECT  1.615 11.484 1.723 11.502 ;
     RECT  1.579 14.382 1.723 16.704 ;
     RECT  1.183 17.766 1.723 17.784 ;
     RECT  0.859 18.54 1.723 19.908 ;
     RECT  0.895 21.402 1.723 21.42 ;
     RECT  1.615 22.752 1.723 33.3 ;
     RECT  1.579 34.164 1.723 35.964 ;
     RECT  1.507 37.062 1.723 37.89 ;
     RECT  1.327 42.732 1.723 43.668 ;
     RECT  1.579 13.446 1.759 13.464 ;
     RECT  1.723 22.752 1.759 38.034 ;
     RECT  1.291 39.024 1.759 39.618 ;
     RECT  1.723 42.264 1.759 43.668 ;
     RECT  1.723 11.484 1.795 12.24 ;
     RECT  1.759 13.374 2.119 13.464 ;
     RECT  1.723 14.382 2.119 17.784 ;
     RECT  1.831 9.63 2.155 9.648 ;
     RECT  1.687 4.23 2.16 6.408 ;
     RECT  0.139 7.362 2.16 7.38 ;
     RECT  2.155 9.594 2.16 9.648 ;
     RECT  1.399 10.71 2.16 10.728 ;
     RECT  1.795 11.484 2.16 12.348 ;
     RECT  2.119 13.374 2.16 17.784 ;
     RECT  1.723 18.54 2.16 21.69 ;
     RECT  1.759 22.752 2.16 39.618 ;
     RECT  1.759 41.724 2.16 43.668 ;
     RECT  0.563 46.008 2.16 46.368 ;
     RECT  0.931 47.736 2.16 50.148 ;
     RECT  2.16 2.151 12.96 62.649 ;
     RECT  12.96 23.706 13.595 60.264 ;
     RECT  13.595 23.706 13.631 60.174 ;
     RECT  12.96 5.436 13.667 22.806 ;
     RECT  13.631 23.706 13.667 59.994 ;
     RECT  13.667 23.706 13.703 25.884 ;
     RECT  13.667 50.436 13.811 58.914 ;
     RECT  13.703 23.706 13.955 25.47 ;
     RECT  13.667 9.792 14.207 22.806 ;
     RECT  13.955 23.706 14.207 24.354 ;
     RECT  13.955 25.146 14.207 25.47 ;
     RECT  13.667 34.866 14.207 47.574 ;
     RECT  13.811 50.796 14.207 58.914 ;
     RECT  13.667 5.706 14.243 5.724 ;
     RECT  14.207 9.792 14.243 20.034 ;
     RECT  14.207 21.096 14.243 21.114 ;
     RECT  14.207 22.176 14.243 22.806 ;
     RECT  14.207 23.796 14.243 24.354 ;
     RECT  14.207 25.146 14.243 25.434 ;
     RECT  13.667 26.766 14.243 30.366 ;
     RECT  13.667 31.158 14.243 34.074 ;
     RECT  14.207 34.866 14.243 44.604 ;
     RECT  14.207 45.666 14.243 47.574 ;
     RECT  13.667 48.366 14.243 49.572 ;
     RECT  14.207 50.796 14.243 51.192 ;
     RECT  14.207 52.146 14.243 57.024 ;
     RECT  14.207 58.086 14.243 58.104 ;
     RECT  14.207 58.896 14.243 58.914 ;
     RECT  13.667 59.976 14.243 59.994 ;
     RECT  14.243 16.506 14.279 16.524 ;
     RECT  14.243 22.716 14.279 22.806 ;
     RECT  14.243 11.376 14.963 11.394 ;
     RECT  14.243 12.528 14.963 12.546 ;
     RECT  14.243 13.644 14.963 13.662 ;
     RECT  14.243 18.774 14.963 18.792 ;
     RECT  14.279 22.716 14.963 22.734 ;
     RECT  14.243 26.766 14.963 26.784 ;
     RECT  14.243 31.896 14.963 31.914 ;
     RECT  14.243 47.286 14.963 47.304 ;
    LAYER M3 ;
     RECT  2.415 2.143 2.505 2.413 ;
     RECT  5.115 2.143 5.205 2.413 ;
     RECT  7.815 2.143 7.905 2.413 ;
     RECT  10.515 2.143 10.605 2.413 ;
     RECT  2.415 2.413 2.697 4.261 ;
     RECT  2.415 4.261 2.754 4.459 ;
     RECT  0.144 4.225 0.162 4.495 ;
     RECT  2.415 4.459 2.862 4.531 ;
     RECT  0.144 4.495 0.198 4.765 ;
     RECT  2.415 4.531 2.898 4.765 ;
     RECT  2.415 4.765 2.934 4.801 ;
     RECT  7.815 2.413 8.097 4.801 ;
     RECT  7.815 4.801 8.262 4.999 ;
     RECT  6.66 4.999 8.262 5.035 ;
     RECT  5.115 2.413 5.397 5.071 ;
     RECT  4.608 5.071 5.397 5.197 ;
     RECT  6.228 5.035 8.262 5.197 ;
     RECT  2.376 4.801 3.042 5.224 ;
     RECT  4.608 5.197 8.262 5.225 ;
     RECT  2.376 5.224 3.186 5.233 ;
     RECT  4.788 5.225 8.262 5.267 ;
     RECT  2.376 5.233 3.402 5.305 ;
     RECT  7.092 5.267 8.262 5.305 ;
     RECT  7.092 5.305 8.91 5.431 ;
     RECT  9.648 3.979 9.666 5.431 ;
     RECT  1.692 5.305 4.05 5.495 ;
     RECT  12.06 5.161 12.078 5.611 ;
     RECT  13.644 5.419 13.662 5.659 ;
     RECT  11.7 5.611 12.078 5.701 ;
     RECT  13.644 5.659 14.238 5.729 ;
     RECT  11.7 5.701 12.15 5.873 ;
     RECT  4.788 5.267 6.282 5.971 ;
     RECT  0.144 4.765 0.234 6.029 ;
     RECT  12.06 5.873 12.15 6.035 ;
     RECT  4.14 5.971 6.282 6.115 ;
     RECT  7.092 5.431 9.666 6.115 ;
     RECT  1.692 5.495 3.402 6.241 ;
     RECT  4.14 6.115 9.666 6.241 ;
     RECT  1.692 6.241 9.666 6.385 ;
     RECT  0.144 6.029 0.198 6.413 ;
     RECT  1.656 6.385 9.666 6.691 ;
     RECT  10.515 2.413 10.797 6.691 ;
     RECT  12.06 6.035 12.078 6.781 ;
     RECT  0.18 6.413 0.198 7.037 ;
     RECT  12.06 6.781 12.15 7.051 ;
     RECT  1.656 6.691 10.797 7.115 ;
     RECT  12.06 7.051 12.258 7.159 ;
     RECT  12.024 7.159 12.258 7.223 ;
     RECT  12.024 7.223 12.15 7.385 ;
     RECT  0.144 7.357 0.162 7.469 ;
     RECT  1.656 7.115 5.814 8.239 ;
     RECT  6.66 7.115 10.797 8.239 ;
     RECT  0.144 8.635 0.162 8.765 ;
     RECT  12.132 7.385 12.15 9.113 ;
     RECT  1.656 8.239 10.797 9.239 ;
     RECT  13.644 5.729 13.662 9.533 ;
     RECT  9.648 9.239 10.797 9.931 ;
     RECT  12.6 10.021 12.618 10.121 ;
     RECT  1.656 9.239 8.73 10.201 ;
     RECT  1.656 10.201 8.802 10.291 ;
     RECT  9.648 9.931 10.89 10.291 ;
     RECT  1.656 10.291 10.89 10.355 ;
     RECT  1.656 10.355 10.797 10.391 ;
     RECT  1.656 10.391 8.55 10.705 ;
     RECT  11.952 10.471 11.97 10.895 ;
     RECT  11.988 11.101 12.618 11.201 ;
     RECT  1.404 10.705 8.55 11.209 ;
     RECT  9.54 10.391 10.797 11.209 ;
     RECT  14.22 9.787 14.238 11.371 ;
     RECT  14.22 11.371 14.958 11.453 ;
     RECT  1.404 11.209 10.797 11.641 ;
     RECT  11.988 11.201 12.006 11.641 ;
     RECT  1.404 11.641 12.006 11.741 ;
     RECT  11.7 11.741 12.006 11.939 ;
     RECT  11.88 11.939 12.006 11.975 ;
     RECT  11.988 11.975 12.006 12.181 ;
     RECT  11.988 12.181 12.618 12.281 ;
     RECT  14.22 11.453 14.238 12.523 ;
     RECT  14.22 12.523 14.958 12.56 ;
     RECT  11.988 12.281 12.006 12.785 ;
     RECT  1.404 11.741 10.854 13.055 ;
     RECT  1.404 13.055 10.797 13.199 ;
     RECT  12.6 13.261 12.618 13.639 ;
     RECT  14.22 12.56 14.238 13.639 ;
     RECT  14.22 13.639 14.958 13.901 ;
     RECT  11.952 13.639 12.618 13.937 ;
     RECT  6.192 13.199 10.797 13.945 ;
     RECT  1.404 13.199 5.397 14.071 ;
     RECT  6.192 13.945 10.89 14.071 ;
     RECT  1.404 14.071 10.89 14.215 ;
     RECT  1.404 14.215 11.178 14.485 ;
     RECT  12.276 13.937 12.618 14.521 ;
     RECT  1.404 14.485 11.394 14.719 ;
     RECT  1.152 14.719 11.394 14.864 ;
     RECT  1.26 14.864 11.394 14.909 ;
     RECT  14.22 13.901 14.238 14.971 ;
     RECT  1.26 14.909 11.178 14.981 ;
     RECT  0.144 14.377 0.162 15.005 ;
     RECT  12.276 14.521 12.69 15.151 ;
     RECT  14.184 14.971 14.238 15.259 ;
     RECT  13.644 15.259 14.238 15.449 ;
     RECT  12.06 15.151 12.69 15.601 ;
     RECT  12.06 15.601 12.762 15.755 ;
     RECT  1.26 14.981 10.89 15.835 ;
     RECT  12.06 15.755 12.618 15.835 ;
     RECT  1.26 15.835 12.618 15.899 ;
     RECT  0.144 16.171 0.162 16.301 ;
     RECT  14.22 15.449 14.238 16.363 ;
     RECT  1.26 15.899 11.466 16.375 ;
     RECT  13.644 16.363 14.238 16.501 ;
     RECT  1.224 16.375 11.466 16.603 ;
     RECT  12.528 15.899 12.618 16.645 ;
     RECT  1.152 16.603 11.466 16.795 ;
     RECT  0.9 16.795 11.466 16.835 ;
     RECT  13.644 16.501 14.274 16.925 ;
     RECT  13.644 16.925 14.238 16.979 ;
     RECT  12.456 16.645 12.618 17.041 ;
     RECT  0.9 16.835 11.43 17.105 ;
     RECT  12.384 17.041 12.618 17.375 ;
     RECT  0.9 17.105 10.998 17.411 ;
     RECT  12.528 17.375 12.618 17.645 ;
     RECT  0.9 17.411 10.818 17.879 ;
     RECT  12.528 17.645 12.546 17.915 ;
     RECT  0.9 17.879 10.797 18.235 ;
     RECT  0.828 18.235 10.797 18.427 ;
     RECT  14.22 16.979 14.238 18.523 ;
     RECT  14.184 18.523 14.238 18.563 ;
     RECT  12.204 18.535 12.222 18.571 ;
     RECT  12.096 18.571 12.222 18.661 ;
     RECT  0.144 18.427 10.797 18.769 ;
     RECT  11.952 18.661 12.222 18.769 ;
     RECT  14.22 18.563 14.238 18.769 ;
     RECT  14.22 18.769 14.958 18.845 ;
     RECT  0.144 18.769 12.222 18.995 ;
     RECT  0.144 18.995 11.394 19.139 ;
     RECT  0.144 19.139 11.142 19.265 ;
     RECT  0.144 19.265 10.926 19.469 ;
     RECT  14.22 18.845 14.238 20.443 ;
     RECT  0.828 19.469 10.926 20.461 ;
     RECT  0.828 20.461 11.07 20.695 ;
     RECT  0.828 20.695 11.214 21.155 ;
     RECT  9.396 21.155 11.214 21.235 ;
     RECT  9.396 21.235 11.43 21.389 ;
     RECT  14.184 20.443 14.238 21.835 ;
     RECT  12.6 19.201 12.618 21.973 ;
     RECT  0.828 21.155 8.586 22.045 ;
     RECT  9.396 21.389 11.214 22.123 ;
     RECT  12.348 21.973 12.618 22.123 ;
     RECT  0.828 22.045 8.658 22.207 ;
     RECT  9.396 22.123 12.618 22.207 ;
     RECT  14.184 21.835 14.274 22.363 ;
     RECT  0.828 22.207 12.618 22.585 ;
     RECT  13.932 22.363 14.274 22.621 ;
     RECT  13.68 22.621 14.274 22.711 ;
     RECT  13.68 22.711 14.958 22.811 ;
     RECT  0.828 22.585 12.834 22.891 ;
     RECT  14.94 22.811 14.958 22.973 ;
     RECT  13.68 22.811 13.95 23.213 ;
     RECT  0.144 22.891 12.834 23.501 ;
     RECT  13.932 23.213 13.95 23.701 ;
     RECT  13.932 23.701 14.202 23.755 ;
     RECT  13.932 23.755 14.238 24.359 ;
     RECT  0.144 23.501 12.474 24.701 ;
     RECT  13.932 24.359 14.202 24.781 ;
     RECT  13.68 24.781 14.202 24.893 ;
     RECT  14.184 24.893 14.202 25.099 ;
     RECT  14.184 25.099 14.238 25.439 ;
     RECT  12.456 24.701 12.474 25.519 ;
     RECT  0.144 24.701 11.682 25.555 ;
     RECT  12.456 25.519 12.618 25.555 ;
     RECT  14.184 25.439 14.202 25.709 ;
     RECT  0.144 25.555 12.618 25.825 ;
     RECT  13.68 25.861 13.698 25.997 ;
     RECT  0.144 25.825 12.654 26.203 ;
     RECT  0.144 26.203 13.662 26.528 ;
     RECT  0.144 26.528 13.086 26.591 ;
     RECT  14.94 26.761 14.958 26.813 ;
     RECT  0.144 26.591 12.618 26.825 ;
     RECT  14.22 27.019 14.238 27.307 ;
     RECT  14.184 27.307 14.238 27.595 ;
     RECT  0.144 26.825 12.078 27.643 ;
     RECT  13.644 27.595 14.238 27.779 ;
     RECT  0.144 27.643 12.294 27.913 ;
     RECT  0.108 27.913 12.294 28.381 ;
     RECT  0.108 28.381 12.51 28.481 ;
     RECT  0.108 28.481 12.078 29.335 ;
     RECT  0.108 29.335 12.474 29.731 ;
     RECT  14.22 27.779 14.238 30.371 ;
     RECT  0.108 29.731 12.51 30.415 ;
     RECT  13.644 30.613 13.662 30.911 ;
     RECT  0.108 30.415 12.618 31.379 ;
     RECT  14.22 31.144 14.238 31.675 ;
     RECT  13.644 31.675 14.238 31.891 ;
     RECT  13.644 31.891 14.958 31.997 ;
     RECT  0.108 31.379 12.582 32.341 ;
     RECT  13.644 31.997 14.238 32.729 ;
     RECT  0.108 32.341 12.834 33.043 ;
     RECT  0.072 33.043 12.834 33.101 ;
     RECT  0.072 33.101 12.582 33.377 ;
     RECT  13.86 32.729 14.238 33.883 ;
     RECT  0.072 33.377 12.402 34.195 ;
     RECT  0.072 34.195 12.654 34.349 ;
     RECT  13.788 33.883 14.238 34.459 ;
     RECT  13.644 34.459 14.238 34.619 ;
     RECT  0.072 34.349 12.042 34.763 ;
     RECT  7.596 34.763 12.042 35.581 ;
     RECT  0.072 34.763 6.822 35.851 ;
     RECT  7.596 35.581 12.186 35.851 ;
     RECT  0.072 35.851 12.186 36.509 ;
     RECT  7.632 36.509 12.186 36.751 ;
     RECT  7.632 36.751 12.222 36.851 ;
     RECT  0.072 36.509 6.822 37.597 ;
     RECT  7.632 36.851 12.186 37.597 ;
     RECT  14.22 34.619 14.238 38.299 ;
     RECT  0.072 37.597 12.186 38.479 ;
     RECT  13.644 38.299 14.238 38.507 ;
     RECT  0.072 38.479 12.402 38.551 ;
     RECT  0.072 38.551 12.474 38.705 ;
     RECT  0.072 38.705 12.186 40.801 ;
     RECT  0.072 40.801 12.402 41.251 ;
     RECT  14.22 38.507 14.238 41.275 ;
     RECT  0.072 41.251 12.654 41.945 ;
     RECT  0.072 41.945 12.618 42.763 ;
     RECT  0.036 42.763 12.618 43.331 ;
     RECT  13.644 41.275 14.238 43.529 ;
     RECT  0.036 43.331 12.402 44.141 ;
     RECT  0.036 44.141 12.186 44.645 ;
     RECT  5.04 44.645 12.186 45.023 ;
     RECT  5.076 45.023 12.186 45.031 ;
     RECT  14.22 43.529 14.238 45.112 ;
     RECT  5.076 45.031 12.258 45.229 ;
     RECT  5.076 45.229 12.294 45.301 ;
     RECT  0.036 44.645 4.302 45.403 ;
     RECT  5.076 45.301 12.438 45.403 ;
     RECT  5.076 45.403 13.086 45.491 ;
     RECT  14.184 45.112 14.238 45.691 ;
     RECT  5.076 45.491 12.618 45.725 ;
     RECT  0.036 45.403 4.338 45.769 ;
     RECT  5.076 45.725 12.474 45.769 ;
     RECT  13.644 45.691 14.238 45.869 ;
     RECT  0.036 45.769 12.474 46.409 ;
     RECT  13.68 45.869 14.238 47.069 ;
     RECT  0.036 46.409 12.078 47.213 ;
     RECT  14.22 47.069 14.238 47.281 ;
     RECT  4.896 47.213 12.078 47.309 ;
     RECT  14.22 47.281 14.958 47.357 ;
     RECT  0.036 47.213 4.086 47.615 ;
     RECT  5.115 47.309 12.078 47.651 ;
     RECT  14.22 47.357 14.238 47.821 ;
     RECT  13.644 47.821 14.238 47.885 ;
     RECT  8.82 47.651 12.078 48.271 ;
     RECT  13.104 48.091 13.122 48.271 ;
     RECT  8.82 48.271 13.122 48.461 ;
     RECT  5.115 47.651 8.097 48.569 ;
     RECT  8.82 48.461 12.474 49.441 ;
     RECT  8.82 49.441 12.618 49.541 ;
     RECT  14.22 47.885 14.238 49.577 ;
     RECT  13.644 49.771 13.662 50.093 ;
     RECT  8.82 49.541 12.258 50.395 ;
     RECT  0.036 47.615 3.87 50.429 ;
     RECT  13.788 50.347 13.806 50.459 ;
     RECT  0.036 50.429 3.294 50.729 ;
     RECT  5.115 48.569 6.102 50.729 ;
     RECT  8.82 50.395 12.474 50.875 ;
     RECT  8.82 50.875 13.086 50.927 ;
     RECT  14.22 50.635 14.238 51.691 ;
     RECT  8.82 50.927 12.654 52.205 ;
     RECT  14.184 51.691 14.238 52.249 ;
     RECT  13.644 52.249 14.238 52.301 ;
     RECT  14.184 52.301 14.238 52.439 ;
     RECT  8.82 52.205 12.618 52.475 ;
     RECT  0.108 50.729 3.294 52.681 ;
     RECT  7.308 48.569 8.097 53.249 ;
     RECT  7.416 53.249 8.097 55.319 ;
     RECT  8.82 52.475 12.078 55.525 ;
     RECT  8.82 55.525 12.51 55.795 ;
     RECT  8.82 55.795 12.582 55.949 ;
     RECT  0.036 52.681 3.294 56.141 ;
     RECT  14.22 52.439 14.238 56.347 ;
     RECT  10.515 55.949 12.582 56.371 ;
     RECT  8.82 55.949 9.738 56.489 ;
     RECT  10.515 56.371 12.618 56.525 ;
     RECT  13.644 56.347 14.238 56.669 ;
     RECT  0.144 56.141 3.294 56.957 ;
     RECT  9.72 56.489 9.738 57.299 ;
     RECT  0.144 56.957 1.386 57.389 ;
     RECT  10.515 56.525 12.078 57.451 ;
     RECT  14.22 56.669 14.238 57.451 ;
     RECT  10.515 57.451 12.51 57.541 ;
     RECT  8.82 56.489 8.874 57.569 ;
     RECT  2.415 56.957 3.294 57.677 ;
     RECT  10.515 57.541 12.582 57.713 ;
     RECT  0.144 57.389 1.35 57.773 ;
     RECT  14.184 57.451 14.238 58.027 ;
     RECT  0.324 57.773 1.35 58.397 ;
     RECT  10.515 57.713 12.51 58.531 ;
     RECT  8.82 57.569 8.838 58.649 ;
     RECT  0.324 58.397 0.918 58.829 ;
     RECT  13.644 58.027 14.238 58.843 ;
     RECT  0.396 58.829 0.918 59.021 ;
     RECT  0.396 59.021 0.522 59.213 ;
     RECT  13.608 58.843 14.238 59.371 ;
     RECT  0.504 59.213 0.522 59.405 ;
     RECT  10.515 58.531 12.654 59.459 ;
     RECT  11.664 59.459 12.654 59.603 ;
     RECT  5.115 50.729 6.03 59.729 ;
     RECT  11.664 59.603 12.402 59.801 ;
     RECT  11.952 59.801 12.402 59.999 ;
     RECT  13.572 59.371 14.238 59.999 ;
     RECT  12.06 59.999 12.402 60.071 ;
     RECT  13.572 59.999 13.626 60.179 ;
     RECT  13.572 60.179 13.59 60.269 ;
     RECT  12.06 60.071 12.078 60.305 ;
     RECT  2.415 57.677 2.697 62.387 ;
     RECT  5.115 59.729 5.397 62.387 ;
     RECT  7.815 55.319 8.097 62.387 ;
     RECT  10.515 59.459 10.797 62.387 ;
     RECT  2.415 62.387 2.505 62.657 ;
     RECT  5.115 62.387 5.205 62.657 ;
     RECT  7.815 62.387 7.905 62.657 ;
     RECT  10.515 62.387 10.605 62.657 ;
    LAYER M4 ;
     RECT  0.085 1.392 0.108 1.416 ;
     RECT  0.085 27.504 0.108 27.528 ;
     RECT  0.061 45.648 0.108 45.672 ;
     RECT  0.025 55.536 0.108 56.136 ;
     RECT  0.108 5.424 0.173 59.4 ;
     RECT  0.173 5.568 0.209 22.728 ;
     RECT  0.173 23.712 0.209 59.4 ;
     RECT  0.209 25.776 0.533 59.4 ;
     RECT  0.209 24.528 0.569 24.552 ;
     RECT  0.533 25.776 0.569 59.016 ;
     RECT  0.569 26.544 0.929 59.016 ;
     RECT  0.929 26.544 1.001 58.392 ;
     RECT  1.001 49.008 1.037 58.392 ;
     RECT  1.001 26.544 1.073 48.024 ;
     RECT  1.037 49.2 1.109 58.392 ;
     RECT  1.109 49.824 1.145 58.392 ;
     RECT  1.145 50.304 1.361 58.392 ;
     RECT  0.209 5.808 2.245 22.728 ;
     RECT  2.245 5.808 2.293 22.824 ;
     RECT  2.293 5.04 2.365 22.824 ;
     RECT  2.365 5.04 2.408 22.872 ;
     RECT  2.329 24.912 2.408 25.032 ;
     RECT  1.073 26.544 2.408 47.208 ;
     RECT  1.361 50.304 2.408 57.672 ;
     RECT  2.408 2.148 2.512 62.652 ;
     RECT  2.512 2.418 2.704 62.382 ;
     RECT  2.704 24.672 2.765 40.056 ;
     RECT  2.704 43.824 2.765 45.192 ;
     RECT  2.765 37.344 2.801 40.056 ;
     RECT  2.704 11.76 2.867 13.128 ;
     RECT  2.801 37.344 2.867 39.864 ;
     RECT  2.765 24.672 2.873 35.928 ;
     RECT  2.704 41.52 2.909 42.312 ;
     RECT  2.704 54.096 2.945 54.984 ;
     RECT  2.873 34.944 2.953 35.928 ;
     RECT  2.867 37.392 2.981 39.864 ;
     RECT  2.945 54.096 2.981 54.12 ;
     RECT  2.953 34.944 3.017 35.784 ;
     RECT  2.765 43.824 3.017 43.848 ;
     RECT  2.704 52.752 3.053 52.776 ;
     RECT  2.981 37.632 3.089 39.864 ;
     RECT  2.704 51.456 3.125 51.48 ;
     RECT  2.704 6.432 3.161 8.568 ;
     RECT  2.704 5.232 3.197 5.256 ;
     RECT  3.089 38.688 3.197 39.864 ;
     RECT  3.089 37.632 3.203 37.656 ;
     RECT  2.867 12.096 3.269 13.128 ;
     RECT  3.197 39.504 3.305 39.864 ;
     RECT  2.704 57.648 3.305 57.672 ;
     RECT  3.161 6.432 3.341 8.472 ;
     RECT  3.017 35.328 3.413 35.784 ;
     RECT  3.341 6.432 3.485 6.456 ;
     RECT  2.704 50.304 3.485 50.424 ;
     RECT  2.704 14.112 3.557 23.688 ;
     RECT  3.269 12.096 3.629 12.12 ;
     RECT  3.557 14.112 3.629 15.336 ;
     RECT  2.704 46.272 3.665 47.208 ;
     RECT  2.704 10.32 3.877 10.344 ;
     RECT  3.557 16.416 3.877 23.688 ;
     RECT  2.873 24.672 3.877 33.672 ;
     RECT  2.765 45.168 3.877 45.192 ;
     RECT  3.877 16.416 3.881 33.672 ;
     RECT  3.485 50.4 3.881 50.424 ;
     RECT  3.341 7.776 3.917 8.472 ;
     RECT  3.629 14.112 3.989 15.288 ;
     RECT  3.881 30.192 4.025 33.672 ;
     RECT  3.877 10.32 4.061 10.392 ;
     RECT  3.989 14.112 4.061 15.048 ;
     RECT  3.881 16.416 4.067 29.16 ;
     RECT  3.917 8.352 4.133 8.472 ;
     RECT  2.909 41.52 4.201 41.544 ;
     RECT  4.025 33.648 4.237 33.672 ;
     RECT  4.237 33.648 4.453 34.2 ;
     RECT  3.413 35.328 4.453 35.592 ;
     RECT  4.093 42.768 4.796 42.792 ;
     RECT  3.877 45.168 4.796 45.432 ;
     RECT  4.453 33.648 4.849 35.592 ;
     RECT  4.133 8.352 4.981 8.376 ;
     RECT  4.067 23.328 5.029 29.16 ;
     RECT  4.025 30.192 5.029 32.232 ;
     RECT  5.029 23.328 5.065 32.232 ;
     RECT  4.849 33.648 5.065 36.024 ;
     RECT  4.957 6.816 5.108 6.84 ;
     RECT  4.981 8.16 5.108 8.376 ;
     RECT  4.061 10.368 5.108 10.392 ;
     RECT  3.269 13.104 5.108 13.128 ;
     RECT  4.061 14.928 5.108 15.048 ;
     RECT  4.067 16.416 5.108 22.344 ;
     RECT  5.065 23.328 5.108 36.024 ;
     RECT  4.813 38.448 5.108 38.472 ;
     RECT  3.841 40.032 5.108 40.056 ;
     RECT  4.201 41.232 5.108 41.544 ;
     RECT  4.796 42.768 5.108 44.184 ;
     RECT  4.796 45.168 5.108 45.816 ;
     RECT  3.665 47.184 5.108 47.208 ;
     RECT  5.108 2.148 5.212 62.652 ;
     RECT  5.212 2.418 5.404 62.382 ;
     RECT  5.404 24.48 5.645 29.784 ;
     RECT  5.404 14.208 5.753 23.352 ;
     RECT  5.645 24.528 5.753 29.784 ;
     RECT  5.404 37.488 5.843 38.472 ;
     RECT  5.404 40.032 5.843 40.056 ;
     RECT  5.404 5.664 5.897 6.36 ;
     RECT  5.753 16.896 5.897 23.208 ;
     RECT  5.753 26.736 5.897 29.784 ;
     RECT  5.404 31.344 5.897 33.768 ;
     RECT  5.404 36 5.897 36.072 ;
     RECT  5.843 37.824 5.897 38.472 ;
     RECT  5.897 31.92 5.939 33.768 ;
     RECT  5.897 37.824 5.969 37.848 ;
     RECT  5.897 17.088 6.041 23.208 ;
     RECT  5.897 26.736 6.131 28.968 ;
     RECT  5.753 14.208 6.265 15.864 ;
     RECT  5.939 31.92 6.275 33.672 ;
     RECT  5.897 6.336 6.293 6.36 ;
     RECT  5.404 12.912 6.365 13.08 ;
     RECT  6.265 14.256 6.365 15.864 ;
     RECT  6.041 17.088 6.409 22.824 ;
     RECT  6.389 30.24 6.473 30.264 ;
     RECT  6.275 31.92 6.473 32.76 ;
     RECT  5.753 24.528 6.515 25.608 ;
     RECT  6.131 26.736 6.581 28.44 ;
     RECT  6.515 24.528 6.611 25.032 ;
     RECT  6.409 17.088 6.617 21.336 ;
     RECT  6.617 20.064 6.659 21.336 ;
     RECT  6.659 21.12 6.697 21.336 ;
     RECT  6.697 21.312 6.725 21.336 ;
     RECT  5.404 9.504 6.755 11.928 ;
     RECT  6.709 7.92 6.796 7.944 ;
     RECT  6.755 10.128 6.797 11.928 ;
     RECT  6.469 38.88 6.797 38.904 ;
     RECT  6.797 10.224 7.369 11.928 ;
     RECT  6.365 12.912 7.369 12.936 ;
     RECT  6.409 22.8 7.441 22.824 ;
     RECT  6.365 15.12 7.521 15.864 ;
     RECT  6.617 17.088 7.532 18.744 ;
     RECT  6.793 5.232 7.808 5.256 ;
     RECT  7.369 10.224 7.808 12.936 ;
     RECT  7.521 14.928 7.808 15.864 ;
     RECT  7.532 17.04 7.808 18.744 ;
     RECT  6.659 20.064 7.808 20.088 ;
     RECT  7.441 21.936 7.808 22.824 ;
     RECT  6.611 24.816 7.808 25.032 ;
     RECT  6.757 26.016 7.808 26.136 ;
     RECT  6.581 27.12 7.808 28.44 ;
     RECT  7.477 30.912 7.808 30.936 ;
     RECT  6.473 32.304 7.808 32.472 ;
     RECT  5.897 36.048 7.808 36.072 ;
     RECT  7.808 2.148 7.912 62.652 ;
     RECT  7.912 2.418 8.104 62.382 ;
     RECT  8.104 20.976 8.165 22.824 ;
     RECT  8.104 25.008 8.165 28.44 ;
     RECT  8.104 14.928 8.237 15 ;
     RECT  8.104 12.576 8.243 13.704 ;
     RECT  8.165 20.976 8.243 22.344 ;
     RECT  8.165 25.632 8.243 27.192 ;
     RECT  8.104 30.048 8.243 30.936 ;
     RECT  8.104 32.304 8.243 32.52 ;
     RECT  8.104 38.736 8.243 39.528 ;
     RECT  8.104 40.56 8.243 40.584 ;
     RECT  8.243 12.576 8.273 13.464 ;
     RECT  8.243 32.304 8.273 32.328 ;
     RECT  8.237 14.928 8.381 14.952 ;
     RECT  8.243 25.632 8.417 25.656 ;
     RECT  8.243 30.816 8.453 30.84 ;
     RECT  8.273 12.576 8.597 12.6 ;
     RECT  8.104 18.72 8.921 18.744 ;
     RECT  8.243 26.736 9.389 27.192 ;
     RECT  9.389 26.736 9.461 26.76 ;
     RECT  9.637 3.984 10.508 4.008 ;
     RECT  8.165 28.416 10.508 28.44 ;
     RECT  10.321 45.552 10.508 45.576 ;
     RECT  10.508 2.148 10.612 62.652 ;
     RECT  10.612 2.418 10.804 62.382 ;
     RECT  10.804 45.552 11.363 45.576 ;
     RECT  10.804 58.704 11.377 58.728 ;
     RECT  10.804 32.064 12.593 32.088 ;
     RECT  10.804 22.128 12.805 22.68 ;
     RECT  12.445 24.048 12.805 24.072 ;
     RECT  13.561 59.376 13.597 59.4 ;
     RECT  13.057 26.208 13.633 26.232 ;
     RECT  12.805 33.072 13.633 33.096 ;
     RECT  13.057 45.408 13.633 45.432 ;
     RECT  13.093 48.432 13.633 48.456 ;
     RECT  13.057 50.88 13.633 50.904 ;
     RECT  13.597 58.848 13.633 59.4 ;
     RECT  12.805 22.128 13.669 24.072 ;
     RECT  13.633 26.208 13.669 26.52 ;
     RECT  13.633 45.408 13.669 45.72 ;
     RECT  13.633 47.856 13.669 48.456 ;
     RECT  13.633 30.624 13.777 33.096 ;
     RECT  13.633 34.464 13.777 34.488 ;
     RECT  13.633 15.264 14.173 15.288 ;
     RECT  13.669 22.128 14.173 24.888 ;
     RECT  13.669 25.968 14.173 26.52 ;
     RECT  13.633 27.6 14.173 27.624 ;
     RECT  13.669 45.408 14.173 48.456 ;
     RECT  13.633 49.776 14.173 50.904 ;
     RECT  13.633 52.272 14.173 52.296 ;
     RECT  13.633 58.032 14.173 59.4 ;
     RECT  13.633 5.424 14.209 9.528 ;
     RECT  14.173 14.976 14.209 15.288 ;
     RECT  13.633 16.368 14.209 16.392 ;
     RECT  14.173 18.528 14.209 18.552 ;
     RECT  14.173 20.448 14.209 27.624 ;
     RECT  13.777 30.624 14.209 34.488 ;
     RECT  13.633 38.304 14.209 38.328 ;
     RECT  13.633 41.28 14.209 43.512 ;
     RECT  14.173 45.12 14.209 48.456 ;
     RECT  14.173 49.776 14.209 52.296 ;
     RECT  13.633 56.352 14.209 56.376 ;
     RECT  14.173 57.456 14.209 59.4 ;
     RECT  14.209 5.424 15.036 59.4 ;
    LAYER M5 ;
     RECT  0.192 1.285 0.216 1.381 ;
     RECT  0.096 1.381 0.216 1.427 ;
     RECT  2.4 2.137 2.52 2.151 ;
     RECT  5.1 2.137 5.22 2.151 ;
     RECT  7.8 2.137 7.92 2.151 ;
     RECT  9.696 2.137 10.62 2.151 ;
     RECT  9.696 2.151 10.812 4.019 ;
     RECT  2.4 2.151 2.712 5.029 ;
     RECT  5.1 2.151 5.412 5.653 ;
     RECT  5.1 5.653 5.544 6.323 ;
     RECT  5.1 6.323 5.412 6.805 ;
     RECT  2.304 5.029 2.712 7.381 ;
     RECT  2.304 7.381 3.288 7.765 ;
     RECT  4.992 6.805 5.412 8.195 ;
     RECT  5.1 8.195 5.412 10.117 ;
     RECT  6.72 7.909 6.744 10.117 ;
     RECT  5.1 10.117 6.744 10.213 ;
     RECT  7.8 2.151 8.112 10.213 ;
     RECT  5.1 10.213 8.112 10.979 ;
     RECT  5.1 10.979 6.216 11.123 ;
     RECT  7.8 10.979 8.112 13.045 ;
     RECT  7.8 13.045 8.232 13.715 ;
     RECT  5.1 11.123 5.544 14.197 ;
     RECT  7.8 13.715 8.112 14.917 ;
     RECT  2.304 7.765 3.816 16.549 ;
     RECT  5.1 14.197 6.216 17.077 ;
     RECT  7.584 14.917 8.112 17.077 ;
     RECT  5.1 17.077 8.112 17.173 ;
     RECT  2.208 16.549 3.816 17.557 ;
     RECT  4.848 17.173 8.112 17.557 ;
     RECT  2.208 17.557 8.112 18.131 ;
     RECT  0.096 1.427 0.12 18.133 ;
     RECT  7.584 18.131 8.112 18.467 ;
     RECT  2.208 18.131 6.504 18.851 ;
     RECT  0.096 18.133 0.216 19.091 ;
     RECT  2.208 18.851 6.36 19.715 ;
     RECT  2.304 19.715 6.36 20.389 ;
     RECT  7.8 18.467 8.112 20.965 ;
     RECT  2.304 20.389 6.648 21.155 ;
     RECT  2.304 21.155 6.6 21.781 ;
     RECT  2.256 21.781 6.6 22.355 ;
     RECT  7.8 20.965 8.232 22.355 ;
     RECT  2.256 22.355 4.056 22.835 ;
     RECT  2.304 22.835 4.056 23.075 ;
     RECT  2.304 23.075 3.96 24.469 ;
     RECT  5.1 22.355 6.6 24.563 ;
     RECT  7.8 22.355 8.112 25.621 ;
     RECT  2.304 24.469 4.008 26.005 ;
     RECT  5.1 24.563 6.504 26.005 ;
     RECT  2.304 26.005 6.504 26.051 ;
     RECT  0.096 19.091 0.12 26.629 ;
     RECT  7.8 25.621 8.232 26.771 ;
     RECT  4.8 26.051 6.504 27.347 ;
     RECT  5.1 27.347 6.504 27.395 ;
     RECT  0.096 26.629 0.84 27.539 ;
     RECT  2.304 26.051 3.816 28.405 ;
     RECT  5.1 27.395 6.456 28.405 ;
     RECT  7.8 26.771 8.112 30.037 ;
     RECT  2.304 28.405 6.456 30.275 ;
     RECT  7.8 30.037 8.232 32.531 ;
     RECT  0.816 27.539 0.84 33.541 ;
     RECT  2.304 30.275 6.264 33.541 ;
     RECT  0.816 33.541 6.264 33.683 ;
     RECT  4.464 33.683 5.928 34.883 ;
     RECT  5.1 34.883 5.928 36.083 ;
     RECT  0.816 33.683 3.192 37.667 ;
     RECT  7.8 32.531 8.112 38.725 ;
     RECT  5.1 36.083 5.832 40.067 ;
     RECT  7.8 38.725 8.232 40.595 ;
     RECT  5.1 40.067 5.412 43.285 ;
     RECT  10.5 4.019 10.812 45.541 ;
     RECT  4.848 43.285 5.412 47.219 ;
     RECT  0.816 37.667 2.712 48.419 ;
     RECT  1.392 48.419 2.712 53.507 ;
     RECT  1.968 53.507 2.712 53.699 ;
     RECT  10.5 45.541 11.352 58.739 ;
     RECT  2.4 53.699 2.712 62.649 ;
     RECT  5.1 47.219 5.412 62.649 ;
     RECT  7.8 40.595 8.112 62.649 ;
     RECT  10.5 58.739 10.812 62.649 ;
     RECT  2.4 62.649 2.52 62.663 ;
     RECT  5.1 62.649 5.22 62.663 ;
     RECT  7.8 62.649 7.92 62.663 ;
     RECT  10.5 62.649 10.62 62.663 ;
     RECT  3.816 7.765 4.992 8.195 ;
     RECT  5.412 7.909 6.72 10.117 ;
     RECT  6.744 7.909 7.8 10.213 ;
     RECT  3.816 8.195 5.1 17.173 ;
     RECT  6.216 14.917 7.584 17.077 ;
     RECT  3.816 17.173 4.848 17.557 ;
     RECT  6.504 18.131 7.584 18.467 ;
     RECT  6.504 18.467 7.8 18.851 ;
     RECT  6.36 18.851 7.8 20.389 ;
     RECT  6.648 20.389 7.8 21.155 ;
     RECT  6.6 21.155 7.8 24.563 ;
     RECT  4.056 22.355 5.1 23.075 ;
     RECT  3.96 23.075 5.1 24.469 ;
     RECT  4.008 24.469 5.1 26.005 ;
     RECT  6.504 24.563 7.8 27.395 ;
     RECT  3.816 26.051 4.8 27.347 ;
     RECT  0.84 26.629 2.304 33.541 ;
     RECT  3.816 27.347 5.1 28.405 ;
     RECT  6.456 27.395 7.8 30.275 ;
     RECT  3.192 33.683 4.464 34.883 ;
  END
END qwen_tx_rnep_r1
END LIBRARY
